VERSION 5.8 ;
BUSBITCHARS "[]" ;
DIVIDERCHAR "/" ;
UNITS
    DATABASE MICRONS 1000 ;
END UNITS

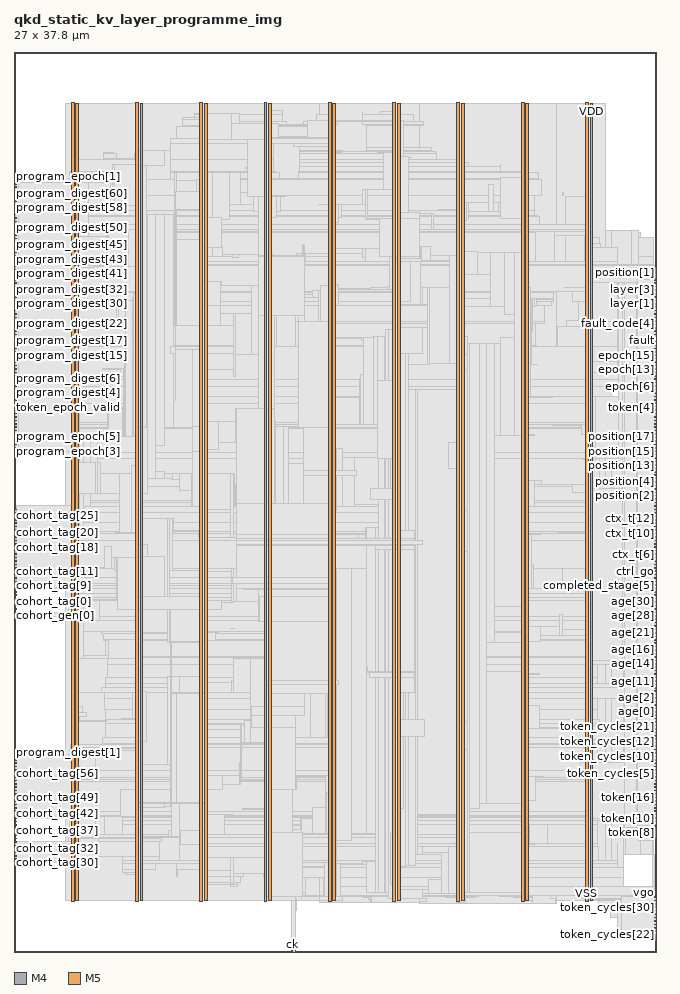
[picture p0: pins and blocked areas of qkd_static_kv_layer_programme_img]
MACRO qkd_static_kv_layer_programme_img
  FOREIGN qkd_static_kv_layer_programme_img 0 0 ;
  CLASS BLOCK ;
  SIZE 27 BY 37.8 ;
  PIN active
    DIRECTION OUTPUT ;
    USE SIGNAL ;
    PORT
      LAYER M4 ;
        RECT  26.916 9.936 27 9.96 ;
    END
  END active
  PIN age[0]
    DIRECTION OUTPUT ;
    USE SIGNAL ;
    PORT
      LAYER M4 ;
        RECT  26.916 10.08 27 10.104 ;
    END
  END age[0]
  PIN age[10]
    DIRECTION OUTPUT ;
    USE SIGNAL ;
    PORT
      LAYER M4 ;
        RECT  26.916 11.52 27 11.544 ;
    END
  END age[10]
  PIN age[11]
    DIRECTION OUTPUT ;
    USE SIGNAL ;
    PORT
      LAYER M4 ;
        RECT  26.916 11.664 27 11.688 ;
    END
  END age[11]
  PIN age[12]
    DIRECTION OUTPUT ;
    USE SIGNAL ;
    PORT
      LAYER M4 ;
        RECT  26.916 11.808 27 11.832 ;
    END
  END age[12]
  PIN age[13]
    DIRECTION OUTPUT ;
    USE SIGNAL ;
    PORT
      LAYER M4 ;
        RECT  26.916 11.952 27 11.976 ;
    END
  END age[13]
  PIN age[14]
    DIRECTION OUTPUT ;
    USE SIGNAL ;
    PORT
      LAYER M4 ;
        RECT  26.916 12.096 27 12.12 ;
    END
  END age[14]
  PIN age[15]
    DIRECTION OUTPUT ;
    USE SIGNAL ;
    PORT
      LAYER M4 ;
        RECT  26.916 12.24 27 12.264 ;
    END
  END age[15]
  PIN age[16]
    DIRECTION OUTPUT ;
    USE SIGNAL ;
    PORT
      LAYER M4 ;
        RECT  26.916 12.384 27 12.408 ;
    END
  END age[16]
  PIN age[17]
    DIRECTION OUTPUT ;
    USE SIGNAL ;
    PORT
      LAYER M4 ;
        RECT  26.916 12.528 27 12.552 ;
    END
  END age[17]
  PIN age[18]
    DIRECTION OUTPUT ;
    USE SIGNAL ;
    PORT
      LAYER M4 ;
        RECT  26.916 12.672 27 12.696 ;
    END
  END age[18]
  PIN age[19]
    DIRECTION OUTPUT ;
    USE SIGNAL ;
    PORT
      LAYER M4 ;
        RECT  26.916 12.816 27 12.84 ;
    END
  END age[19]
  PIN age[1]
    DIRECTION OUTPUT ;
    USE SIGNAL ;
    PORT
      LAYER M4 ;
        RECT  26.916 10.224 27 10.248 ;
    END
  END age[1]
  PIN age[20]
    DIRECTION OUTPUT ;
    USE SIGNAL ;
    PORT
      LAYER M4 ;
        RECT  26.916 12.96 27 12.984 ;
    END
  END age[20]
  PIN age[21]
    DIRECTION OUTPUT ;
    USE SIGNAL ;
    PORT
      LAYER M4 ;
        RECT  26.916 13.104 27 13.128 ;
    END
  END age[21]
  PIN age[22]
    DIRECTION OUTPUT ;
    USE SIGNAL ;
    PORT
      LAYER M4 ;
        RECT  26.916 13.248 27 13.272 ;
    END
  END age[22]
  PIN age[23]
    DIRECTION OUTPUT ;
    USE SIGNAL ;
    PORT
      LAYER M4 ;
        RECT  26.916 13.392 27 13.416 ;
    END
  END age[23]
  PIN age[24]
    DIRECTION OUTPUT ;
    USE SIGNAL ;
    PORT
      LAYER M4 ;
        RECT  26.916 13.536 27 13.56 ;
    END
  END age[24]
  PIN age[25]
    DIRECTION OUTPUT ;
    USE SIGNAL ;
    PORT
      LAYER M4 ;
        RECT  26.916 13.68 27 13.704 ;
    END
  END age[25]
  PIN age[26]
    DIRECTION OUTPUT ;
    USE SIGNAL ;
    PORT
      LAYER M4 ;
        RECT  26.916 13.824 27 13.848 ;
    END
  END age[26]
  PIN age[27]
    DIRECTION OUTPUT ;
    USE SIGNAL ;
    PORT
      LAYER M4 ;
        RECT  26.916 13.968 27 13.992 ;
    END
  END age[27]
  PIN age[28]
    DIRECTION OUTPUT ;
    USE SIGNAL ;
    PORT
      LAYER M4 ;
        RECT  26.916 14.112 27 14.136 ;
    END
  END age[28]
  PIN age[29]
    DIRECTION OUTPUT ;
    USE SIGNAL ;
    PORT
      LAYER M4 ;
        RECT  26.916 14.256 27 14.28 ;
    END
  END age[29]
  PIN age[2]
    DIRECTION OUTPUT ;
    USE SIGNAL ;
    PORT
      LAYER M4 ;
        RECT  26.916 10.368 27 10.392 ;
    END
  END age[2]
  PIN age[30]
    DIRECTION OUTPUT ;
    USE SIGNAL ;
    PORT
      LAYER M4 ;
        RECT  26.916 14.4 27 14.424 ;
    END
  END age[30]
  PIN age[31]
    DIRECTION OUTPUT ;
    USE SIGNAL ;
    PORT
      LAYER M4 ;
        RECT  26.916 14.544 27 14.568 ;
    END
  END age[31]
  PIN age[3]
    DIRECTION OUTPUT ;
    USE SIGNAL ;
    PORT
      LAYER M4 ;
        RECT  26.916 10.512 27 10.536 ;
    END
  END age[3]
  PIN age[4]
    DIRECTION OUTPUT ;
    USE SIGNAL ;
    PORT
      LAYER M4 ;
        RECT  26.916 10.656 27 10.68 ;
    END
  END age[4]
  PIN age[5]
    DIRECTION OUTPUT ;
    USE SIGNAL ;
    PORT
      LAYER M4 ;
        RECT  26.916 10.8 27 10.824 ;
    END
  END age[5]
  PIN age[6]
    DIRECTION OUTPUT ;
    USE SIGNAL ;
    PORT
      LAYER M4 ;
        RECT  26.916 10.944 27 10.968 ;
    END
  END age[6]
  PIN age[7]
    DIRECTION OUTPUT ;
    USE SIGNAL ;
    PORT
      LAYER M4 ;
        RECT  26.916 11.088 27 11.112 ;
    END
  END age[7]
  PIN age[8]
    DIRECTION OUTPUT ;
    USE SIGNAL ;
    PORT
      LAYER M4 ;
        RECT  26.916 11.232 27 11.256 ;
    END
  END age[8]
  PIN age[9]
    DIRECTION OUTPUT ;
    USE SIGNAL ;
    PORT
      LAYER M4 ;
        RECT  26.916 11.376 27 11.4 ;
    END
  END age[9]
  PIN attention_issue
    DIRECTION OUTPUT ;
    USE SIGNAL ;
    PORT
      LAYER M4 ;
        RECT  26.916 14.688 27 14.712 ;
    END
  END attention_issue
  PIN attention_run
    DIRECTION OUTPUT ;
    USE SIGNAL ;
    PORT
      LAYER M4 ;
        RECT  26.916 14.832 27 14.856 ;
    END
  END attention_run
  PIN ck
    DIRECTION INPUT ;
    USE SIGNAL ;
    PORT
      LAYER M5 ;
        RECT  11.664 0 11.688 0.084 ;
    END
  END ck
  PIN cohort_gen[0]
    DIRECTION INPUT ;
    USE SIGNAL ;
    PORT
      LAYER M4 ;
        RECT  0 14.112 0.084 14.136 ;
    END
  END cohort_gen[0]
  PIN cohort_gen[1]
    DIRECTION INPUT ;
    USE SIGNAL ;
    PORT
      LAYER M4 ;
        RECT  0 14.256 0.084 14.28 ;
    END
  END cohort_gen[1]
  PIN cohort_tag[0]
    DIRECTION INPUT ;
    USE SIGNAL ;
    PORT
      LAYER M4 ;
        RECT  0 14.4 0.084 14.424 ;
    END
  END cohort_tag[0]
  PIN cohort_tag[10]
    DIRECTION INPUT ;
    USE SIGNAL ;
    PORT
      LAYER M4 ;
        RECT  0 15.84 0.084 15.864 ;
    END
  END cohort_tag[10]
  PIN cohort_tag[11]
    DIRECTION INPUT ;
    USE SIGNAL ;
    PORT
      LAYER M4 ;
        RECT  0 15.984 0.084 16.008 ;
    END
  END cohort_tag[11]
  PIN cohort_tag[12]
    DIRECTION INPUT ;
    USE SIGNAL ;
    PORT
      LAYER M4 ;
        RECT  0 16.128 0.084 16.152 ;
    END
  END cohort_tag[12]
  PIN cohort_tag[13]
    DIRECTION INPUT ;
    USE SIGNAL ;
    PORT
      LAYER M4 ;
        RECT  0 16.272 0.084 16.296 ;
    END
  END cohort_tag[13]
  PIN cohort_tag[14]
    DIRECTION INPUT ;
    USE SIGNAL ;
    PORT
      LAYER M4 ;
        RECT  0 16.416 0.084 16.44 ;
    END
  END cohort_tag[14]
  PIN cohort_tag[15]
    DIRECTION INPUT ;
    USE SIGNAL ;
    PORT
      LAYER M4 ;
        RECT  0 16.56 0.084 16.584 ;
    END
  END cohort_tag[15]
  PIN cohort_tag[16]
    DIRECTION INPUT ;
    USE SIGNAL ;
    PORT
      LAYER M4 ;
        RECT  0 16.704 0.084 16.728 ;
    END
  END cohort_tag[16]
  PIN cohort_tag[17]
    DIRECTION INPUT ;
    USE SIGNAL ;
    PORT
      LAYER M4 ;
        RECT  0 16.848 0.084 16.872 ;
    END
  END cohort_tag[17]
  PIN cohort_tag[18]
    DIRECTION INPUT ;
    USE SIGNAL ;
    PORT
      LAYER M4 ;
        RECT  0 16.992 0.084 17.016 ;
    END
  END cohort_tag[18]
  PIN cohort_tag[19]
    DIRECTION INPUT ;
    USE SIGNAL ;
    PORT
      LAYER M4 ;
        RECT  0 17.136 0.084 17.16 ;
    END
  END cohort_tag[19]
  PIN cohort_tag[1]
    DIRECTION INPUT ;
    USE SIGNAL ;
    PORT
      LAYER M4 ;
        RECT  0 14.544 0.084 14.568 ;
    END
  END cohort_tag[1]
  PIN cohort_tag[20]
    DIRECTION INPUT ;
    USE SIGNAL ;
    PORT
      LAYER M4 ;
        RECT  0 17.28 0.084 17.304 ;
    END
  END cohort_tag[20]
  PIN cohort_tag[21]
    DIRECTION INPUT ;
    USE SIGNAL ;
    PORT
      LAYER M4 ;
        RECT  0 17.424 0.084 17.448 ;
    END
  END cohort_tag[21]
  PIN cohort_tag[22]
    DIRECTION INPUT ;
    USE SIGNAL ;
    PORT
      LAYER M4 ;
        RECT  0 17.568 0.084 17.592 ;
    END
  END cohort_tag[22]
  PIN cohort_tag[23]
    DIRECTION INPUT ;
    USE SIGNAL ;
    PORT
      LAYER M4 ;
        RECT  0 17.712 0.084 17.736 ;
    END
  END cohort_tag[23]
  PIN cohort_tag[24]
    DIRECTION INPUT ;
    USE SIGNAL ;
    PORT
      LAYER M4 ;
        RECT  0 17.856 0.084 17.88 ;
    END
  END cohort_tag[24]
  PIN cohort_tag[25]
    DIRECTION INPUT ;
    USE SIGNAL ;
    PORT
      LAYER M4 ;
        RECT  0 18 0.084 18.024 ;
    END
  END cohort_tag[25]
  PIN cohort_tag[26]
    DIRECTION INPUT ;
    USE SIGNAL ;
    PORT
      LAYER M4 ;
        RECT  0 18.144 0.084 18.168 ;
    END
  END cohort_tag[26]
  PIN cohort_tag[27]
    DIRECTION INPUT ;
    USE SIGNAL ;
    PORT
      LAYER M4 ;
        RECT  0 18.288 0.084 18.312 ;
    END
  END cohort_tag[27]
  PIN cohort_tag[28]
    DIRECTION INPUT ;
    USE SIGNAL ;
    PORT
      LAYER M4 ;
        RECT  0 18.432 0.084 18.456 ;
    END
  END cohort_tag[28]
  PIN cohort_tag[29]
    DIRECTION INPUT ;
    USE SIGNAL ;
    PORT
      LAYER M4 ;
        RECT  0 18.576 0.084 18.6 ;
    END
  END cohort_tag[29]
  PIN cohort_tag[2]
    DIRECTION INPUT ;
    USE SIGNAL ;
    PORT
      LAYER M4 ;
        RECT  0 14.688 0.084 14.712 ;
    END
  END cohort_tag[2]
  PIN cohort_tag[30]
    DIRECTION INPUT ;
    USE SIGNAL ;
    PORT
      LAYER M4 ;
        RECT  0 3.744 0.084 3.768 ;
    END
  END cohort_tag[30]
  PIN cohort_tag[31]
    DIRECTION INPUT ;
    USE SIGNAL ;
    PORT
      LAYER M4 ;
        RECT  0 3.888 0.084 3.912 ;
    END
  END cohort_tag[31]
  PIN cohort_tag[32]
    DIRECTION INPUT ;
    USE SIGNAL ;
    PORT
      LAYER M4 ;
        RECT  0 4.032 0.084 4.056 ;
    END
  END cohort_tag[32]
  PIN cohort_tag[33]
    DIRECTION INPUT ;
    USE SIGNAL ;
    PORT
      LAYER M4 ;
        RECT  0 4.176 0.084 4.2 ;
    END
  END cohort_tag[33]
  PIN cohort_tag[34]
    DIRECTION INPUT ;
    USE SIGNAL ;
    PORT
      LAYER M4 ;
        RECT  0 4.32 0.084 4.344 ;
    END
  END cohort_tag[34]
  PIN cohort_tag[35]
    DIRECTION INPUT ;
    USE SIGNAL ;
    PORT
      LAYER M4 ;
        RECT  0 4.464 0.084 4.488 ;
    END
  END cohort_tag[35]
  PIN cohort_tag[36]
    DIRECTION INPUT ;
    USE SIGNAL ;
    PORT
      LAYER M4 ;
        RECT  0 4.608 0.084 4.632 ;
    END
  END cohort_tag[36]
  PIN cohort_tag[37]
    DIRECTION INPUT ;
    USE SIGNAL ;
    PORT
      LAYER M4 ;
        RECT  0 4.752 0.084 4.776 ;
    END
  END cohort_tag[37]
  PIN cohort_tag[38]
    DIRECTION INPUT ;
    USE SIGNAL ;
    PORT
      LAYER M4 ;
        RECT  0 4.896 0.084 4.92 ;
    END
  END cohort_tag[38]
  PIN cohort_tag[39]
    DIRECTION INPUT ;
    USE SIGNAL ;
    PORT
      LAYER M4 ;
        RECT  0 5.04 0.084 5.064 ;
    END
  END cohort_tag[39]
  PIN cohort_tag[3]
    DIRECTION INPUT ;
    USE SIGNAL ;
    PORT
      LAYER M4 ;
        RECT  0 14.832 0.084 14.856 ;
    END
  END cohort_tag[3]
  PIN cohort_tag[40]
    DIRECTION INPUT ;
    USE SIGNAL ;
    PORT
      LAYER M4 ;
        RECT  0 5.184 0.084 5.208 ;
    END
  END cohort_tag[40]
  PIN cohort_tag[41]
    DIRECTION INPUT ;
    USE SIGNAL ;
    PORT
      LAYER M4 ;
        RECT  0 5.328 0.084 5.352 ;
    END
  END cohort_tag[41]
  PIN cohort_tag[42]
    DIRECTION INPUT ;
    USE SIGNAL ;
    PORT
      LAYER M4 ;
        RECT  0 5.472 0.084 5.496 ;
    END
  END cohort_tag[42]
  PIN cohort_tag[43]
    DIRECTION INPUT ;
    USE SIGNAL ;
    PORT
      LAYER M4 ;
        RECT  0 5.616 0.084 5.64 ;
    END
  END cohort_tag[43]
  PIN cohort_tag[44]
    DIRECTION INPUT ;
    USE SIGNAL ;
    PORT
      LAYER M4 ;
        RECT  0 5.76 0.084 5.784 ;
    END
  END cohort_tag[44]
  PIN cohort_tag[45]
    DIRECTION INPUT ;
    USE SIGNAL ;
    PORT
      LAYER M4 ;
        RECT  0 5.904 0.084 5.928 ;
    END
  END cohort_tag[45]
  PIN cohort_tag[46]
    DIRECTION INPUT ;
    USE SIGNAL ;
    PORT
      LAYER M4 ;
        RECT  0 6.048 0.084 6.072 ;
    END
  END cohort_tag[46]
  PIN cohort_tag[47]
    DIRECTION INPUT ;
    USE SIGNAL ;
    PORT
      LAYER M4 ;
        RECT  0 6.192 0.084 6.216 ;
    END
  END cohort_tag[47]
  PIN cohort_tag[48]
    DIRECTION INPUT ;
    USE SIGNAL ;
    PORT
      LAYER M4 ;
        RECT  0 6.336 0.084 6.36 ;
    END
  END cohort_tag[48]
  PIN cohort_tag[49]
    DIRECTION INPUT ;
    USE SIGNAL ;
    PORT
      LAYER M4 ;
        RECT  0 6.48 0.084 6.504 ;
    END
  END cohort_tag[49]
  PIN cohort_tag[4]
    DIRECTION INPUT ;
    USE SIGNAL ;
    PORT
      LAYER M4 ;
        RECT  0 14.976 0.084 15 ;
    END
  END cohort_tag[4]
  PIN cohort_tag[50]
    DIRECTION INPUT ;
    USE SIGNAL ;
    PORT
      LAYER M4 ;
        RECT  0 6.624 0.084 6.648 ;
    END
  END cohort_tag[50]
  PIN cohort_tag[51]
    DIRECTION INPUT ;
    USE SIGNAL ;
    PORT
      LAYER M4 ;
        RECT  0 6.768 0.084 6.792 ;
    END
  END cohort_tag[51]
  PIN cohort_tag[52]
    DIRECTION INPUT ;
    USE SIGNAL ;
    PORT
      LAYER M4 ;
        RECT  0 6.912 0.084 6.936 ;
    END
  END cohort_tag[52]
  PIN cohort_tag[53]
    DIRECTION INPUT ;
    USE SIGNAL ;
    PORT
      LAYER M4 ;
        RECT  0 7.056 0.084 7.08 ;
    END
  END cohort_tag[53]
  PIN cohort_tag[54]
    DIRECTION INPUT ;
    USE SIGNAL ;
    PORT
      LAYER M4 ;
        RECT  0 7.2 0.084 7.224 ;
    END
  END cohort_tag[54]
  PIN cohort_tag[55]
    DIRECTION INPUT ;
    USE SIGNAL ;
    PORT
      LAYER M4 ;
        RECT  0 7.344 0.084 7.368 ;
    END
  END cohort_tag[55]
  PIN cohort_tag[56]
    DIRECTION INPUT ;
    USE SIGNAL ;
    PORT
      LAYER M4 ;
        RECT  0 7.488 0.084 7.512 ;
    END
  END cohort_tag[56]
  PIN cohort_tag[57]
    DIRECTION INPUT ;
    USE SIGNAL ;
    PORT
      LAYER M4 ;
        RECT  0 7.632 0.084 7.656 ;
    END
  END cohort_tag[57]
  PIN cohort_tag[58]
    DIRECTION INPUT ;
    USE SIGNAL ;
    PORT
      LAYER M4 ;
        RECT  0 7.776 0.084 7.8 ;
    END
  END cohort_tag[58]
  PIN cohort_tag[5]
    DIRECTION INPUT ;
    USE SIGNAL ;
    PORT
      LAYER M4 ;
        RECT  0 15.12 0.084 15.144 ;
    END
  END cohort_tag[5]
  PIN cohort_tag[6]
    DIRECTION INPUT ;
    USE SIGNAL ;
    PORT
      LAYER M4 ;
        RECT  0 15.264 0.084 15.288 ;
    END
  END cohort_tag[6]
  PIN cohort_tag[7]
    DIRECTION INPUT ;
    USE SIGNAL ;
    PORT
      LAYER M4 ;
        RECT  0 15.408 0.084 15.432 ;
    END
  END cohort_tag[7]
  PIN cohort_tag[8]
    DIRECTION INPUT ;
    USE SIGNAL ;
    PORT
      LAYER M4 ;
        RECT  0 15.552 0.084 15.576 ;
    END
  END cohort_tag[8]
  PIN cohort_tag[9]
    DIRECTION INPUT ;
    USE SIGNAL ;
    PORT
      LAYER M4 ;
        RECT  0 15.696 0.084 15.72 ;
    END
  END cohort_tag[9]
  PIN completed_stage[0]
    DIRECTION OUTPUT ;
    USE SIGNAL ;
    PORT
      LAYER M4 ;
        RECT  26.916 14.976 27 15 ;
    END
  END completed_stage[0]
  PIN completed_stage[1]
    DIRECTION OUTPUT ;
    USE SIGNAL ;
    PORT
      LAYER M4 ;
        RECT  26.916 15.12 27 15.144 ;
    END
  END completed_stage[1]
  PIN completed_stage[2]
    DIRECTION OUTPUT ;
    USE SIGNAL ;
    PORT
      LAYER M4 ;
        RECT  26.916 15.264 27 15.288 ;
    END
  END completed_stage[2]
  PIN completed_stage[3]
    DIRECTION OUTPUT ;
    USE SIGNAL ;
    PORT
      LAYER M4 ;
        RECT  26.916 15.408 27 15.432 ;
    END
  END completed_stage[3]
  PIN completed_stage[4]
    DIRECTION OUTPUT ;
    USE SIGNAL ;
    PORT
      LAYER M4 ;
        RECT  26.916 15.552 27 15.576 ;
    END
  END completed_stage[4]
  PIN completed_stage[5]
    DIRECTION OUTPUT ;
    USE SIGNAL ;
    PORT
      LAYER M4 ;
        RECT  26.916 15.696 27 15.72 ;
    END
  END completed_stage[5]
  PIN configured
    DIRECTION OUTPUT ;
    USE SIGNAL ;
    PORT
      LAYER M4 ;
        RECT  26.916 15.84 27 15.864 ;
    END
  END configured
  PIN ctrl_go
    DIRECTION OUTPUT ;
    USE SIGNAL ;
    PORT
      LAYER M4 ;
        RECT  26.916 15.984 27 16.008 ;
    END
  END ctrl_go
  PIN ctx_t[0]
    DIRECTION OUTPUT ;
    USE SIGNAL ;
    PORT
      LAYER M4 ;
        RECT  26.916 16.128 27 16.152 ;
    END
  END ctx_t[0]
  PIN ctx_t[10]
    DIRECTION OUTPUT ;
    USE SIGNAL ;
    PORT
      LAYER M4 ;
        RECT  26.916 17.568 27 17.592 ;
    END
  END ctx_t[10]
  PIN ctx_t[11]
    DIRECTION OUTPUT ;
    USE SIGNAL ;
    PORT
      LAYER M4 ;
        RECT  26.916 17.712 27 17.736 ;
    END
  END ctx_t[11]
  PIN ctx_t[12]
    DIRECTION OUTPUT ;
    USE SIGNAL ;
    PORT
      LAYER M4 ;
        RECT  26.916 17.856 27 17.88 ;
    END
  END ctx_t[12]
  PIN ctx_t[13]
    DIRECTION OUTPUT ;
    USE SIGNAL ;
    PORT
      LAYER M4 ;
        RECT  26.916 18 27 18.024 ;
    END
  END ctx_t[13]
  PIN ctx_t[1]
    DIRECTION OUTPUT ;
    USE SIGNAL ;
    PORT
      LAYER M4 ;
        RECT  26.916 16.272 27 16.296 ;
    END
  END ctx_t[1]
  PIN ctx_t[2]
    DIRECTION OUTPUT ;
    USE SIGNAL ;
    PORT
      LAYER M4 ;
        RECT  26.916 16.416 27 16.44 ;
    END
  END ctx_t[2]
  PIN ctx_t[3]
    DIRECTION OUTPUT ;
    USE SIGNAL ;
    PORT
      LAYER M4 ;
        RECT  26.916 16.56 27 16.584 ;
    END
  END ctx_t[3]
  PIN ctx_t[4]
    DIRECTION OUTPUT ;
    USE SIGNAL ;
    PORT
      LAYER M4 ;
        RECT  26.916 16.704 27 16.728 ;
    END
  END ctx_t[4]
  PIN ctx_t[5]
    DIRECTION OUTPUT ;
    USE SIGNAL ;
    PORT
      LAYER M4 ;
        RECT  26.916 16.848 27 16.872 ;
    END
  END ctx_t[5]
  PIN ctx_t[6]
    DIRECTION OUTPUT ;
    USE SIGNAL ;
    PORT
      LAYER M4 ;
        RECT  26.916 16.992 27 17.016 ;
    END
  END ctx_t[6]
  PIN ctx_t[7]
    DIRECTION OUTPUT ;
    USE SIGNAL ;
    PORT
      LAYER M4 ;
        RECT  26.916 17.136 27 17.16 ;
    END
  END ctx_t[7]
  PIN ctx_t[8]
    DIRECTION OUTPUT ;
    USE SIGNAL ;
    PORT
      LAYER M4 ;
        RECT  26.916 17.28 27 17.304 ;
    END
  END ctx_t[8]
  PIN ctx_t[9]
    DIRECTION OUTPUT ;
    USE SIGNAL ;
    PORT
      LAYER M4 ;
        RECT  26.916 17.424 27 17.448 ;
    END
  END ctx_t[9]
  PIN done
    DIRECTION OUTPUT ;
    USE SIGNAL ;
    PORT
      LAYER M4 ;
        RECT  26.916 18.144 27 18.168 ;
    END
  END done
  PIN epoch[0]
    DIRECTION OUTPUT ;
    USE SIGNAL ;
    PORT
      LAYER M4 ;
        RECT  26.916 18.288 27 18.312 ;
    END
  END epoch[0]
  PIN epoch[10]
    DIRECTION OUTPUT ;
    USE SIGNAL ;
    PORT
      LAYER M4 ;
        RECT  26.916 24.336 27 24.36 ;
    END
  END epoch[10]
  PIN epoch[11]
    DIRECTION OUTPUT ;
    USE SIGNAL ;
    PORT
      LAYER M4 ;
        RECT  26.916 24.48 27 24.504 ;
    END
  END epoch[11]
  PIN epoch[12]
    DIRECTION OUTPUT ;
    USE SIGNAL ;
    PORT
      LAYER M4 ;
        RECT  26.916 24.624 27 24.648 ;
    END
  END epoch[12]
  PIN epoch[13]
    DIRECTION OUTPUT ;
    USE SIGNAL ;
    PORT
      LAYER M4 ;
        RECT  26.916 24.768 27 24.792 ;
    END
  END epoch[13]
  PIN epoch[14]
    DIRECTION OUTPUT ;
    USE SIGNAL ;
    PORT
      LAYER M4 ;
        RECT  26.916 24.912 27 24.936 ;
    END
  END epoch[14]
  PIN epoch[15]
    DIRECTION OUTPUT ;
    USE SIGNAL ;
    PORT
      LAYER M4 ;
        RECT  26.916 25.056 27 25.08 ;
    END
  END epoch[15]
  PIN epoch[1]
    DIRECTION OUTPUT ;
    USE SIGNAL ;
    PORT
      LAYER M4 ;
        RECT  26.916 18.432 27 18.456 ;
    END
  END epoch[1]
  PIN epoch[2]
    DIRECTION OUTPUT ;
    USE SIGNAL ;
    PORT
      LAYER M4 ;
        RECT  26.916 18.576 27 18.6 ;
    END
  END epoch[2]
  PIN epoch[3]
    DIRECTION OUTPUT ;
    USE SIGNAL ;
    PORT
      LAYER M4 ;
        RECT  26.916 18.72 27 18.744 ;
    END
  END epoch[3]
  PIN epoch[4]
    DIRECTION OUTPUT ;
    USE SIGNAL ;
    PORT
      LAYER M4 ;
        RECT  26.916 18.864 27 18.888 ;
    END
  END epoch[4]
  PIN epoch[5]
    DIRECTION OUTPUT ;
    USE SIGNAL ;
    PORT
      LAYER M4 ;
        RECT  26.916 19.008 27 19.032 ;
    END
  END epoch[5]
  PIN epoch[6]
    DIRECTION OUTPUT ;
    USE SIGNAL ;
    PORT
      LAYER M4 ;
        RECT  26.916 23.76 27 23.784 ;
    END
  END epoch[6]
  PIN epoch[7]
    DIRECTION OUTPUT ;
    USE SIGNAL ;
    PORT
      LAYER M4 ;
        RECT  26.916 23.904 27 23.928 ;
    END
  END epoch[7]
  PIN epoch[8]
    DIRECTION OUTPUT ;
    USE SIGNAL ;
    PORT
      LAYER M4 ;
        RECT  26.916 24.048 27 24.072 ;
    END
  END epoch[8]
  PIN epoch[9]
    DIRECTION OUTPUT ;
    USE SIGNAL ;
    PORT
      LAYER M4 ;
        RECT  26.916 24.192 27 24.216 ;
    END
  END epoch[9]
  PIN expected_upstream_quiet
    DIRECTION OUTPUT ;
    USE SIGNAL ;
    PORT
      LAYER M4 ;
        RECT  26.916 25.2 27 25.224 ;
    END
  END expected_upstream_quiet
  PIN fault
    DIRECTION OUTPUT ;
    USE SIGNAL ;
    PORT
      LAYER M4 ;
        RECT  26.916 25.344 27 25.368 ;
    END
  END fault
  PIN fault_code[0]
    DIRECTION OUTPUT ;
    USE SIGNAL ;
    PORT
      LAYER M4 ;
        RECT  26.916 25.488 27 25.512 ;
    END
  END fault_code[0]
  PIN fault_code[1]
    DIRECTION OUTPUT ;
    USE SIGNAL ;
    PORT
      LAYER M4 ;
        RECT  26.916 25.632 27 25.656 ;
    END
  END fault_code[1]
  PIN fault_code[2]
    DIRECTION OUTPUT ;
    USE SIGNAL ;
    PORT
      LAYER M4 ;
        RECT  26.916 25.776 27 25.8 ;
    END
  END fault_code[2]
  PIN fault_code[3]
    DIRECTION OUTPUT ;
    USE SIGNAL ;
    PORT
      LAYER M4 ;
        RECT  26.916 25.92 27 25.944 ;
    END
  END fault_code[3]
  PIN fault_code[4]
    DIRECTION OUTPUT ;
    USE SIGNAL ;
    PORT
      LAYER M4 ;
        RECT  26.916 26.064 27 26.088 ;
    END
  END fault_code[4]
  PIN fault_code[5]
    DIRECTION OUTPUT ;
    USE SIGNAL ;
    PORT
      LAYER M4 ;
        RECT  26.916 26.208 27 26.232 ;
    END
  END fault_code[5]
  PIN fault_code[6]
    DIRECTION OUTPUT ;
    USE SIGNAL ;
    PORT
      LAYER M4 ;
        RECT  26.916 26.352 27 26.376 ;
    END
  END fault_code[6]
  PIN fault_code[7]
    DIRECTION OUTPUT ;
    USE SIGNAL ;
    PORT
      LAYER M4 ;
        RECT  26.916 26.496 27 26.52 ;
    END
  END fault_code[7]
  PIN generation[0]
    DIRECTION OUTPUT ;
    USE SIGNAL ;
    PORT
      LAYER M4 ;
        RECT  26.916 26.64 27 26.664 ;
    END
  END generation[0]
  PIN generation[1]
    DIRECTION OUTPUT ;
    USE SIGNAL ;
    PORT
      LAYER M4 ;
        RECT  26.916 26.784 27 26.808 ;
    END
  END generation[1]
  PIN kgo
    DIRECTION OUTPUT ;
    USE SIGNAL ;
    PORT
      LAYER M4 ;
        RECT  26.916 26.928 27 26.952 ;
    END
  END kgo
  PIN layer[0]
    DIRECTION OUTPUT ;
    USE SIGNAL ;
    PORT
      LAYER M4 ;
        RECT  26.916 27.072 27 27.096 ;
    END
  END layer[0]
  PIN layer[1]
    DIRECTION OUTPUT ;
    USE SIGNAL ;
    PORT
      LAYER M4 ;
        RECT  26.916 27.216 27 27.24 ;
    END
  END layer[1]
  PIN layer[2]
    DIRECTION OUTPUT ;
    USE SIGNAL ;
    PORT
      LAYER M4 ;
        RECT  26.916 27.36 27 27.384 ;
    END
  END layer[2]
  PIN layer[3]
    DIRECTION OUTPUT ;
    USE SIGNAL ;
    PORT
      LAYER M4 ;
        RECT  26.916 27.504 27 27.528 ;
    END
  END layer[3]
  PIN layer[4]
    DIRECTION OUTPUT ;
    USE SIGNAL ;
    PORT
      LAYER M4 ;
        RECT  26.916 27.648 27 27.672 ;
    END
  END layer[4]
  PIN layer[5]
    DIRECTION OUTPUT ;
    USE SIGNAL ;
    PORT
      LAYER M4 ;
        RECT  26.916 27.792 27 27.816 ;
    END
  END layer[5]
  PIN link_start
    DIRECTION OUTPUT ;
    USE SIGNAL ;
    PORT
      LAYER M4 ;
        RECT  26.916 27.936 27 27.96 ;
    END
  END link_start
  PIN position[0]
    DIRECTION OUTPUT ;
    USE SIGNAL ;
    PORT
      LAYER M4 ;
        RECT  26.916 28.08 27 28.104 ;
    END
  END position[0]
  PIN position[10]
    DIRECTION OUTPUT ;
    USE SIGNAL ;
    PORT
      LAYER M4 ;
        RECT  26.916 20.304 27 20.328 ;
    END
  END position[10]
  PIN position[11]
    DIRECTION OUTPUT ;
    USE SIGNAL ;
    PORT
      LAYER M4 ;
        RECT  26.916 20.448 27 20.472 ;
    END
  END position[11]
  PIN position[12]
    DIRECTION OUTPUT ;
    USE SIGNAL ;
    PORT
      LAYER M4 ;
        RECT  26.916 20.592 27 20.616 ;
    END
  END position[12]
  PIN position[13]
    DIRECTION OUTPUT ;
    USE SIGNAL ;
    PORT
      LAYER M4 ;
        RECT  26.916 20.736 27 20.76 ;
    END
  END position[13]
  PIN position[14]
    DIRECTION OUTPUT ;
    USE SIGNAL ;
    PORT
      LAYER M4 ;
        RECT  26.916 20.88 27 20.904 ;
    END
  END position[14]
  PIN position[15]
    DIRECTION OUTPUT ;
    USE SIGNAL ;
    PORT
      LAYER M4 ;
        RECT  26.916 21.024 27 21.048 ;
    END
  END position[15]
  PIN position[16]
    DIRECTION OUTPUT ;
    USE SIGNAL ;
    PORT
      LAYER M4 ;
        RECT  26.916 21.168 27 21.192 ;
    END
  END position[16]
  PIN position[17]
    DIRECTION OUTPUT ;
    USE SIGNAL ;
    PORT
      LAYER M4 ;
        RECT  26.916 21.312 27 21.336 ;
    END
  END position[17]
  PIN position[1]
    DIRECTION OUTPUT ;
    USE SIGNAL ;
    PORT
      LAYER M4 ;
        RECT  26.916 28.224 27 28.248 ;
    END
  END position[1]
  PIN position[2]
    DIRECTION OUTPUT ;
    USE SIGNAL ;
    PORT
      LAYER M4 ;
        RECT  26.916 19.152 27 19.176 ;
    END
  END position[2]
  PIN position[3]
    DIRECTION OUTPUT ;
    USE SIGNAL ;
    PORT
      LAYER M4 ;
        RECT  26.916 19.296 27 19.32 ;
    END
  END position[3]
  PIN position[4]
    DIRECTION OUTPUT ;
    USE SIGNAL ;
    PORT
      LAYER M4 ;
        RECT  26.916 19.44 27 19.464 ;
    END
  END position[4]
  PIN position[5]
    DIRECTION OUTPUT ;
    USE SIGNAL ;
    PORT
      LAYER M4 ;
        RECT  26.916 19.584 27 19.608 ;
    END
  END position[5]
  PIN position[6]
    DIRECTION OUTPUT ;
    USE SIGNAL ;
    PORT
      LAYER M4 ;
        RECT  26.916 19.728 27 19.752 ;
    END
  END position[6]
  PIN position[7]
    DIRECTION OUTPUT ;
    USE SIGNAL ;
    PORT
      LAYER M4 ;
        RECT  26.916 19.872 27 19.896 ;
    END
  END position[7]
  PIN position[8]
    DIRECTION OUTPUT ;
    USE SIGNAL ;
    PORT
      LAYER M4 ;
        RECT  26.916 20.016 27 20.04 ;
    END
  END position[8]
  PIN position[9]
    DIRECTION OUTPUT ;
    USE SIGNAL ;
    PORT
      LAYER M4 ;
        RECT  26.916 20.16 27 20.184 ;
    END
  END position[9]
  PIN program_digest[0]
    DIRECTION INPUT ;
    USE SIGNAL ;
    PORT
      LAYER M4 ;
        RECT  0 7.92 0.084 7.944 ;
    END
  END program_digest[0]
  PIN program_digest[10]
    DIRECTION INPUT ;
    USE SIGNAL ;
    PORT
      LAYER M4 ;
        RECT  0 24.336 0.084 24.36 ;
    END
  END program_digest[10]
  PIN program_digest[11]
    DIRECTION INPUT ;
    USE SIGNAL ;
    PORT
      LAYER M4 ;
        RECT  0 24.48 0.084 24.504 ;
    END
  END program_digest[11]
  PIN program_digest[12]
    DIRECTION INPUT ;
    USE SIGNAL ;
    PORT
      LAYER M4 ;
        RECT  0 24.624 0.084 24.648 ;
    END
  END program_digest[12]
  PIN program_digest[13]
    DIRECTION INPUT ;
    USE SIGNAL ;
    PORT
      LAYER M4 ;
        RECT  0 24.768 0.084 24.792 ;
    END
  END program_digest[13]
  PIN program_digest[14]
    DIRECTION INPUT ;
    USE SIGNAL ;
    PORT
      LAYER M4 ;
        RECT  0 24.912 0.084 24.936 ;
    END
  END program_digest[14]
  PIN program_digest[15]
    DIRECTION INPUT ;
    USE SIGNAL ;
    PORT
      LAYER M4 ;
        RECT  0 25.056 0.084 25.08 ;
    END
  END program_digest[15]
  PIN program_digest[16]
    DIRECTION INPUT ;
    USE SIGNAL ;
    PORT
      LAYER M4 ;
        RECT  0 25.2 0.084 25.224 ;
    END
  END program_digest[16]
  PIN program_digest[17]
    DIRECTION INPUT ;
    USE SIGNAL ;
    PORT
      LAYER M4 ;
        RECT  0 25.344 0.084 25.368 ;
    END
  END program_digest[17]
  PIN program_digest[18]
    DIRECTION INPUT ;
    USE SIGNAL ;
    PORT
      LAYER M4 ;
        RECT  0 25.488 0.084 25.512 ;
    END
  END program_digest[18]
  PIN program_digest[19]
    DIRECTION INPUT ;
    USE SIGNAL ;
    PORT
      LAYER M4 ;
        RECT  0 25.632 0.084 25.656 ;
    END
  END program_digest[19]
  PIN program_digest[1]
    DIRECTION INPUT ;
    USE SIGNAL ;
    PORT
      LAYER M4 ;
        RECT  0 8.064 0.084 8.088 ;
    END
  END program_digest[1]
  PIN program_digest[20]
    DIRECTION INPUT ;
    USE SIGNAL ;
    PORT
      LAYER M4 ;
        RECT  0 25.776 0.084 25.8 ;
    END
  END program_digest[20]
  PIN program_digest[21]
    DIRECTION INPUT ;
    USE SIGNAL ;
    PORT
      LAYER M4 ;
        RECT  0 25.92 0.084 25.944 ;
    END
  END program_digest[21]
  PIN program_digest[22]
    DIRECTION INPUT ;
    USE SIGNAL ;
    PORT
      LAYER M4 ;
        RECT  0 26.064 0.084 26.088 ;
    END
  END program_digest[22]
  PIN program_digest[23]
    DIRECTION INPUT ;
    USE SIGNAL ;
    PORT
      LAYER M4 ;
        RECT  0 26.208 0.084 26.232 ;
    END
  END program_digest[23]
  PIN program_digest[24]
    DIRECTION INPUT ;
    USE SIGNAL ;
    PORT
      LAYER M4 ;
        RECT  0 26.352 0.084 26.376 ;
    END
  END program_digest[24]
  PIN program_digest[25]
    DIRECTION INPUT ;
    USE SIGNAL ;
    PORT
      LAYER M4 ;
        RECT  0 26.496 0.084 26.52 ;
    END
  END program_digest[25]
  PIN program_digest[26]
    DIRECTION INPUT ;
    USE SIGNAL ;
    PORT
      LAYER M4 ;
        RECT  0 26.64 0.084 26.664 ;
    END
  END program_digest[26]
  PIN program_digest[27]
    DIRECTION INPUT ;
    USE SIGNAL ;
    PORT
      LAYER M4 ;
        RECT  0 26.784 0.084 26.808 ;
    END
  END program_digest[27]
  PIN program_digest[28]
    DIRECTION INPUT ;
    USE SIGNAL ;
    PORT
      LAYER M4 ;
        RECT  0 26.928 0.084 26.952 ;
    END
  END program_digest[28]
  PIN program_digest[29]
    DIRECTION INPUT ;
    USE SIGNAL ;
    PORT
      LAYER M4 ;
        RECT  0 27.072 0.084 27.096 ;
    END
  END program_digest[29]
  PIN program_digest[2]
    DIRECTION INPUT ;
    USE SIGNAL ;
    PORT
      LAYER M4 ;
        RECT  0 8.208 0.084 8.232 ;
    END
  END program_digest[2]
  PIN program_digest[30]
    DIRECTION INPUT ;
    USE SIGNAL ;
    PORT
      LAYER M4 ;
        RECT  0 27.216 0.084 27.24 ;
    END
  END program_digest[30]
  PIN program_digest[31]
    DIRECTION INPUT ;
    USE SIGNAL ;
    PORT
      LAYER M4 ;
        RECT  0 27.36 0.084 27.384 ;
    END
  END program_digest[31]
  PIN program_digest[32]
    DIRECTION INPUT ;
    USE SIGNAL ;
    PORT
      LAYER M4 ;
        RECT  0 27.504 0.084 27.528 ;
    END
  END program_digest[32]
  PIN program_digest[33]
    DIRECTION INPUT ;
    USE SIGNAL ;
    PORT
      LAYER M4 ;
        RECT  0 27.648 0.084 27.672 ;
    END
  END program_digest[33]
  PIN program_digest[34]
    DIRECTION INPUT ;
    USE SIGNAL ;
    PORT
      LAYER M4 ;
        RECT  0 27.792 0.084 27.816 ;
    END
  END program_digest[34]
  PIN program_digest[35]
    DIRECTION INPUT ;
    USE SIGNAL ;
    PORT
      LAYER M4 ;
        RECT  0 27.936 0.084 27.96 ;
    END
  END program_digest[35]
  PIN program_digest[36]
    DIRECTION INPUT ;
    USE SIGNAL ;
    PORT
      LAYER M4 ;
        RECT  0 28.08 0.084 28.104 ;
    END
  END program_digest[36]
  PIN program_digest[37]
    DIRECTION INPUT ;
    USE SIGNAL ;
    PORT
      LAYER M4 ;
        RECT  0 28.224 0.084 28.248 ;
    END
  END program_digest[37]
  PIN program_digest[38]
    DIRECTION INPUT ;
    USE SIGNAL ;
    PORT
      LAYER M4 ;
        RECT  0 28.368 0.084 28.392 ;
    END
  END program_digest[38]
  PIN program_digest[39]
    DIRECTION INPUT ;
    USE SIGNAL ;
    PORT
      LAYER M4 ;
        RECT  0 28.512 0.084 28.536 ;
    END
  END program_digest[39]
  PIN program_digest[3]
    DIRECTION INPUT ;
    USE SIGNAL ;
    PORT
      LAYER M4 ;
        RECT  0 23.328 0.084 23.352 ;
    END
  END program_digest[3]
  PIN program_digest[40]
    DIRECTION INPUT ;
    USE SIGNAL ;
    PORT
      LAYER M4 ;
        RECT  0 28.656 0.084 28.68 ;
    END
  END program_digest[40]
  PIN program_digest[41]
    DIRECTION INPUT ;
    USE SIGNAL ;
    PORT
      LAYER M4 ;
        RECT  0 28.8 0.084 28.824 ;
    END
  END program_digest[41]
  PIN program_digest[42]
    DIRECTION INPUT ;
    USE SIGNAL ;
    PORT
      LAYER M4 ;
        RECT  0 28.944 0.084 28.968 ;
    END
  END program_digest[42]
  PIN program_digest[43]
    DIRECTION INPUT ;
    USE SIGNAL ;
    PORT
      LAYER M4 ;
        RECT  0 29.088 0.084 29.112 ;
    END
  END program_digest[43]
  PIN program_digest[44]
    DIRECTION INPUT ;
    USE SIGNAL ;
    PORT
      LAYER M4 ;
        RECT  0 29.232 0.084 29.256 ;
    END
  END program_digest[44]
  PIN program_digest[45]
    DIRECTION INPUT ;
    USE SIGNAL ;
    PORT
      LAYER M4 ;
        RECT  0 29.376 0.084 29.4 ;
    END
  END program_digest[45]
  PIN program_digest[46]
    DIRECTION INPUT ;
    USE SIGNAL ;
    PORT
      LAYER M4 ;
        RECT  0 29.52 0.084 29.544 ;
    END
  END program_digest[46]
  PIN program_digest[47]
    DIRECTION INPUT ;
    USE SIGNAL ;
    PORT
      LAYER M4 ;
        RECT  0 29.664 0.084 29.688 ;
    END
  END program_digest[47]
  PIN program_digest[48]
    DIRECTION INPUT ;
    USE SIGNAL ;
    PORT
      LAYER M4 ;
        RECT  0 29.808 0.084 29.832 ;
    END
  END program_digest[48]
  PIN program_digest[49]
    DIRECTION INPUT ;
    USE SIGNAL ;
    PORT
      LAYER M4 ;
        RECT  0 29.952 0.084 29.976 ;
    END
  END program_digest[49]
  PIN program_digest[4]
    DIRECTION INPUT ;
    USE SIGNAL ;
    PORT
      LAYER M4 ;
        RECT  0 23.472 0.084 23.496 ;
    END
  END program_digest[4]
  PIN program_digest[50]
    DIRECTION INPUT ;
    USE SIGNAL ;
    PORT
      LAYER M4 ;
        RECT  0 30.096 0.084 30.12 ;
    END
  END program_digest[50]
  PIN program_digest[51]
    DIRECTION INPUT ;
    USE SIGNAL ;
    PORT
      LAYER M4 ;
        RECT  0 30.24 0.084 30.264 ;
    END
  END program_digest[51]
  PIN program_digest[52]
    DIRECTION INPUT ;
    USE SIGNAL ;
    PORT
      LAYER M4 ;
        RECT  0 30.384 0.084 30.408 ;
    END
  END program_digest[52]
  PIN program_digest[53]
    DIRECTION INPUT ;
    USE SIGNAL ;
    PORT
      LAYER M4 ;
        RECT  0 30.528 0.084 30.552 ;
    END
  END program_digest[53]
  PIN program_digest[54]
    DIRECTION INPUT ;
    USE SIGNAL ;
    PORT
      LAYER M4 ;
        RECT  0 30.672 0.084 30.696 ;
    END
  END program_digest[54]
  PIN program_digest[55]
    DIRECTION INPUT ;
    USE SIGNAL ;
    PORT
      LAYER M4 ;
        RECT  0 30.816 0.084 30.84 ;
    END
  END program_digest[55]
  PIN program_digest[56]
    DIRECTION INPUT ;
    USE SIGNAL ;
    PORT
      LAYER M4 ;
        RECT  0 30.96 0.084 30.984 ;
    END
  END program_digest[56]
  PIN program_digest[57]
    DIRECTION INPUT ;
    USE SIGNAL ;
    PORT
      LAYER M4 ;
        RECT  0 31.104 0.084 31.128 ;
    END
  END program_digest[57]
  PIN program_digest[58]
    DIRECTION INPUT ;
    USE SIGNAL ;
    PORT
      LAYER M4 ;
        RECT  0 31.248 0.084 31.272 ;
    END
  END program_digest[58]
  PIN program_digest[59]
    DIRECTION INPUT ;
    USE SIGNAL ;
    PORT
      LAYER M4 ;
        RECT  0 31.392 0.084 31.416 ;
    END
  END program_digest[59]
  PIN program_digest[5]
    DIRECTION INPUT ;
    USE SIGNAL ;
    PORT
      LAYER M4 ;
        RECT  0 23.616 0.084 23.64 ;
    END
  END program_digest[5]
  PIN program_digest[60]
    DIRECTION INPUT ;
    USE SIGNAL ;
    PORT
      LAYER M4 ;
        RECT  0 31.536 0.084 31.56 ;
    END
  END program_digest[60]
  PIN program_digest[61]
    DIRECTION INPUT ;
    USE SIGNAL ;
    PORT
      LAYER M4 ;
        RECT  0 31.68 0.084 31.704 ;
    END
  END program_digest[61]
  PIN program_digest[62]
    DIRECTION INPUT ;
    USE SIGNAL ;
    PORT
      LAYER M4 ;
        RECT  0 31.824 0.084 31.848 ;
    END
  END program_digest[62]
  PIN program_digest[63]
    DIRECTION INPUT ;
    USE SIGNAL ;
    PORT
      LAYER M4 ;
        RECT  0 31.968 0.084 31.992 ;
    END
  END program_digest[63]
  PIN program_digest[6]
    DIRECTION INPUT ;
    USE SIGNAL ;
    PORT
      LAYER M4 ;
        RECT  0 23.76 0.084 23.784 ;
    END
  END program_digest[6]
  PIN program_digest[7]
    DIRECTION INPUT ;
    USE SIGNAL ;
    PORT
      LAYER M4 ;
        RECT  0 23.904 0.084 23.928 ;
    END
  END program_digest[7]
  PIN program_digest[8]
    DIRECTION INPUT ;
    USE SIGNAL ;
    PORT
      LAYER M4 ;
        RECT  0 24.048 0.084 24.072 ;
    END
  END program_digest[8]
  PIN program_digest[9]
    DIRECTION INPUT ;
    USE SIGNAL ;
    PORT
      LAYER M4 ;
        RECT  0 24.192 0.084 24.216 ;
    END
  END program_digest[9]
  PIN program_epoch[0]
    DIRECTION INPUT ;
    USE SIGNAL ;
    PORT
      LAYER M4 ;
        RECT  0 32.112 0.084 32.136 ;
    END
  END program_epoch[0]
  PIN program_epoch[10]
    DIRECTION INPUT ;
    USE SIGNAL ;
    PORT
      LAYER M4 ;
        RECT  0 22.032 0.084 22.056 ;
    END
  END program_epoch[10]
  PIN program_epoch[11]
    DIRECTION INPUT ;
    USE SIGNAL ;
    PORT
      LAYER M4 ;
        RECT  0 22.176 0.084 22.2 ;
    END
  END program_epoch[11]
  PIN program_epoch[12]
    DIRECTION INPUT ;
    USE SIGNAL ;
    PORT
      LAYER M4 ;
        RECT  0 22.32 0.084 22.344 ;
    END
  END program_epoch[12]
  PIN program_epoch[13]
    DIRECTION INPUT ;
    USE SIGNAL ;
    PORT
      LAYER M4 ;
        RECT  0 22.464 0.084 22.488 ;
    END
  END program_epoch[13]
  PIN program_epoch[14]
    DIRECTION INPUT ;
    USE SIGNAL ;
    PORT
      LAYER M4 ;
        RECT  0 22.608 0.084 22.632 ;
    END
  END program_epoch[14]
  PIN program_epoch[15]
    DIRECTION INPUT ;
    USE SIGNAL ;
    PORT
      LAYER M4 ;
        RECT  0 22.752 0.084 22.776 ;
    END
  END program_epoch[15]
  PIN program_epoch[1]
    DIRECTION INPUT ;
    USE SIGNAL ;
    PORT
      LAYER M4 ;
        RECT  0 32.256 0.084 32.28 ;
    END
  END program_epoch[1]
  PIN program_epoch[2]
    DIRECTION INPUT ;
    USE SIGNAL ;
    PORT
      LAYER M4 ;
        RECT  0 32.4 0.084 32.424 ;
    END
  END program_epoch[2]
  PIN program_epoch[3]
    DIRECTION INPUT ;
    USE SIGNAL ;
    PORT
      LAYER M4 ;
        RECT  0 21.024 0.084 21.048 ;
    END
  END program_epoch[3]
  PIN program_epoch[4]
    DIRECTION INPUT ;
    USE SIGNAL ;
    PORT
      LAYER M4 ;
        RECT  0 21.168 0.084 21.192 ;
    END
  END program_epoch[4]
  PIN program_epoch[5]
    DIRECTION INPUT ;
    USE SIGNAL ;
    PORT
      LAYER M4 ;
        RECT  0 21.312 0.084 21.336 ;
    END
  END program_epoch[5]
  PIN program_epoch[6]
    DIRECTION INPUT ;
    USE SIGNAL ;
    PORT
      LAYER M4 ;
        RECT  0 21.456 0.084 21.48 ;
    END
  END program_epoch[6]
  PIN program_epoch[7]
    DIRECTION INPUT ;
    USE SIGNAL ;
    PORT
      LAYER M4 ;
        RECT  0 21.6 0.084 21.624 ;
    END
  END program_epoch[7]
  PIN program_epoch[8]
    DIRECTION INPUT ;
    USE SIGNAL ;
    PORT
      LAYER M4 ;
        RECT  0 21.744 0.084 21.768 ;
    END
  END program_epoch[8]
  PIN program_epoch[9]
    DIRECTION INPUT ;
    USE SIGNAL ;
    PORT
      LAYER M4 ;
        RECT  0 21.888 0.084 21.912 ;
    END
  END program_epoch[9]
  PIN program_ready
    DIRECTION INPUT ;
    USE SIGNAL ;
    PORT
      LAYER M4 ;
        RECT  0 22.896 0.084 22.92 ;
    END
  END program_ready
  PIN rst_n
    DIRECTION INPUT ;
    USE SIGNAL ;
    PORT
      LAYER M5 ;
        RECT  11.808 0 11.832 0.084 ;
    END
  END rst_n
  PIN stage[0]
    DIRECTION OUTPUT ;
    USE SIGNAL ;
    PORT
      LAYER M4 ;
        RECT  26.916 21.456 27 21.48 ;
    END
  END stage[0]
  PIN stage[1]
    DIRECTION OUTPUT ;
    USE SIGNAL ;
    PORT
      LAYER M4 ;
        RECT  26.916 21.6 27 21.624 ;
    END
  END stage[1]
  PIN stage[2]
    DIRECTION OUTPUT ;
    USE SIGNAL ;
    PORT
      LAYER M4 ;
        RECT  26.916 21.744 27 21.768 ;
    END
  END stage[2]
  PIN stage[3]
    DIRECTION OUTPUT ;
    USE SIGNAL ;
    PORT
      LAYER M4 ;
        RECT  26.916 21.888 27 21.912 ;
    END
  END stage[3]
  PIN stage[4]
    DIRECTION OUTPUT ;
    USE SIGNAL ;
    PORT
      LAYER M4 ;
        RECT  26.916 22.032 27 22.056 ;
    END
  END stage[4]
  PIN stage[5]
    DIRECTION OUTPUT ;
    USE SIGNAL ;
    PORT
      LAYER M4 ;
        RECT  26.916 22.176 27 22.2 ;
    END
  END stage[5]
  PIN stage_done
    DIRECTION OUTPUT ;
    USE SIGNAL ;
    PORT
      LAYER M4 ;
        RECT  26.916 22.32 27 22.344 ;
    END
  END stage_done
  PIN stage_start
    DIRECTION OUTPUT ;
    USE SIGNAL ;
    PORT
      LAYER M4 ;
        RECT  26.916 22.464 27 22.488 ;
    END
  END stage_start
  PIN start
    DIRECTION INPUT ;
    USE SIGNAL ;
    PORT
      LAYER M4 ;
        RECT  0 23.04 0.084 23.064 ;
    END
  END start
  PIN token[0]
    DIRECTION OUTPUT ;
    USE SIGNAL ;
    PORT
      LAYER M4 ;
        RECT  26.916 22.608 27 22.632 ;
    END
  END token[0]
  PIN token[10]
    DIRECTION OUTPUT ;
    USE SIGNAL ;
    PORT
      LAYER M4 ;
        RECT  26.916 5.616 27 5.64 ;
    END
  END token[10]
  PIN token[11]
    DIRECTION OUTPUT ;
    USE SIGNAL ;
    PORT
      LAYER M4 ;
        RECT  26.916 5.76 27 5.784 ;
    END
  END token[11]
  PIN token[12]
    DIRECTION OUTPUT ;
    USE SIGNAL ;
    PORT
      LAYER M4 ;
        RECT  26.916 5.904 27 5.928 ;
    END
  END token[12]
  PIN token[13]
    DIRECTION OUTPUT ;
    USE SIGNAL ;
    PORT
      LAYER M4 ;
        RECT  26.916 6.048 27 6.072 ;
    END
  END token[13]
  PIN token[14]
    DIRECTION OUTPUT ;
    USE SIGNAL ;
    PORT
      LAYER M4 ;
        RECT  26.916 6.192 27 6.216 ;
    END
  END token[14]
  PIN token[15]
    DIRECTION OUTPUT ;
    USE SIGNAL ;
    PORT
      LAYER M4 ;
        RECT  26.916 6.336 27 6.36 ;
    END
  END token[15]
  PIN token[16]
    DIRECTION OUTPUT ;
    USE SIGNAL ;
    PORT
      LAYER M4 ;
        RECT  26.916 6.48 27 6.504 ;
    END
  END token[16]
  PIN token[17]
    DIRECTION OUTPUT ;
    USE SIGNAL ;
    PORT
      LAYER M4 ;
        RECT  26.916 6.624 27 6.648 ;
    END
  END token[17]
  PIN token[1]
    DIRECTION OUTPUT ;
    USE SIGNAL ;
    PORT
      LAYER M4 ;
        RECT  26.916 22.752 27 22.776 ;
    END
  END token[1]
  PIN token[2]
    DIRECTION OUTPUT ;
    USE SIGNAL ;
    PORT
      LAYER M4 ;
        RECT  26.916 22.896 27 22.92 ;
    END
  END token[2]
  PIN token[3]
    DIRECTION OUTPUT ;
    USE SIGNAL ;
    PORT
      LAYER M4 ;
        RECT  26.916 23.04 27 23.064 ;
    END
  END token[3]
  PIN token[4]
    DIRECTION OUTPUT ;
    USE SIGNAL ;
    PORT
      LAYER M4 ;
        RECT  26.916 23.184 27 23.208 ;
    END
  END token[4]
  PIN token[5]
    DIRECTION OUTPUT ;
    USE SIGNAL ;
    PORT
      LAYER M4 ;
        RECT  26.916 23.328 27 23.352 ;
    END
  END token[5]
  PIN token[6]
    DIRECTION OUTPUT ;
    USE SIGNAL ;
    PORT
      LAYER M4 ;
        RECT  26.916 23.472 27 23.496 ;
    END
  END token[6]
  PIN token[7]
    DIRECTION OUTPUT ;
    USE SIGNAL ;
    PORT
      LAYER M4 ;
        RECT  26.916 23.616 27 23.64 ;
    END
  END token[7]
  PIN token[8]
    DIRECTION OUTPUT ;
    USE SIGNAL ;
    PORT
      LAYER M4 ;
        RECT  26.916 5.328 27 5.352 ;
    END
  END token[8]
  PIN token[9]
    DIRECTION OUTPUT ;
    USE SIGNAL ;
    PORT
      LAYER M4 ;
        RECT  26.916 5.472 27 5.496 ;
    END
  END token[9]
  PIN token_cycles[0]
    DIRECTION OUTPUT ;
    USE SIGNAL ;
    PORT
      LAYER M4 ;
        RECT  26.916 6.768 27 6.792 ;
    END
  END token_cycles[0]
  PIN token_cycles[10]
    DIRECTION OUTPUT ;
    USE SIGNAL ;
    PORT
      LAYER M4 ;
        RECT  26.916 8.208 27 8.232 ;
    END
  END token_cycles[10]
  PIN token_cycles[11]
    DIRECTION OUTPUT ;
    USE SIGNAL ;
    PORT
      LAYER M4 ;
        RECT  26.916 8.352 27 8.376 ;
    END
  END token_cycles[11]
  PIN token_cycles[12]
    DIRECTION OUTPUT ;
    USE SIGNAL ;
    PORT
      LAYER M4 ;
        RECT  26.916 8.496 27 8.52 ;
    END
  END token_cycles[12]
  PIN token_cycles[13]
    DIRECTION OUTPUT ;
    USE SIGNAL ;
    PORT
      LAYER M4 ;
        RECT  26.916 8.64 27 8.664 ;
    END
  END token_cycles[13]
  PIN token_cycles[14]
    DIRECTION OUTPUT ;
    USE SIGNAL ;
    PORT
      LAYER M4 ;
        RECT  26.916 8.784 27 8.808 ;
    END
  END token_cycles[14]
  PIN token_cycles[15]
    DIRECTION OUTPUT ;
    USE SIGNAL ;
    PORT
      LAYER M4 ;
        RECT  26.916 8.928 27 8.952 ;
    END
  END token_cycles[15]
  PIN token_cycles[16]
    DIRECTION OUTPUT ;
    USE SIGNAL ;
    PORT
      LAYER M4 ;
        RECT  26.916 9.072 27 9.096 ;
    END
  END token_cycles[16]
  PIN token_cycles[17]
    DIRECTION OUTPUT ;
    USE SIGNAL ;
    PORT
      LAYER M4 ;
        RECT  26.916 9.216 27 9.24 ;
    END
  END token_cycles[17]
  PIN token_cycles[18]
    DIRECTION OUTPUT ;
    USE SIGNAL ;
    PORT
      LAYER M4 ;
        RECT  26.916 9.36 27 9.384 ;
    END
  END token_cycles[18]
  PIN token_cycles[19]
    DIRECTION OUTPUT ;
    USE SIGNAL ;
    PORT
      LAYER M4 ;
        RECT  26.916 9.504 27 9.528 ;
    END
  END token_cycles[19]
  PIN token_cycles[1]
    DIRECTION OUTPUT ;
    USE SIGNAL ;
    PORT
      LAYER M4 ;
        RECT  26.916 6.912 27 6.936 ;
    END
  END token_cycles[1]
  PIN token_cycles[20]
    DIRECTION OUTPUT ;
    USE SIGNAL ;
    PORT
      LAYER M4 ;
        RECT  26.916 9.648 27 9.672 ;
    END
  END token_cycles[20]
  PIN token_cycles[21]
    DIRECTION OUTPUT ;
    USE SIGNAL ;
    PORT
      LAYER M4 ;
        RECT  26.916 9.792 27 9.816 ;
    END
  END token_cycles[21]
  PIN token_cycles[22]
    DIRECTION OUTPUT ;
    USE SIGNAL ;
    PORT
      LAYER M4 ;
        RECT  26.916 0.72 27 0.744 ;
    END
  END token_cycles[22]
  PIN token_cycles[23]
    DIRECTION OUTPUT ;
    USE SIGNAL ;
    PORT
      LAYER M4 ;
        RECT  26.916 0.864 27 0.888 ;
    END
  END token_cycles[23]
  PIN token_cycles[24]
    DIRECTION OUTPUT ;
    USE SIGNAL ;
    PORT
      LAYER M4 ;
        RECT  26.916 1.008 27 1.032 ;
    END
  END token_cycles[24]
  PIN token_cycles[25]
    DIRECTION OUTPUT ;
    USE SIGNAL ;
    PORT
      LAYER M4 ;
        RECT  26.916 1.152 27 1.176 ;
    END
  END token_cycles[25]
  PIN token_cycles[26]
    DIRECTION OUTPUT ;
    USE SIGNAL ;
    PORT
      LAYER M4 ;
        RECT  26.916 1.296 27 1.32 ;
    END
  END token_cycles[26]
  PIN token_cycles[27]
    DIRECTION OUTPUT ;
    USE SIGNAL ;
    PORT
      LAYER M4 ;
        RECT  26.916 1.44 27 1.464 ;
    END
  END token_cycles[27]
  PIN token_cycles[28]
    DIRECTION OUTPUT ;
    USE SIGNAL ;
    PORT
      LAYER M4 ;
        RECT  26.916 1.584 27 1.608 ;
    END
  END token_cycles[28]
  PIN token_cycles[29]
    DIRECTION OUTPUT ;
    USE SIGNAL ;
    PORT
      LAYER M4 ;
        RECT  26.916 1.728 27 1.752 ;
    END
  END token_cycles[29]
  PIN token_cycles[2]
    DIRECTION OUTPUT ;
    USE SIGNAL ;
    PORT
      LAYER M4 ;
        RECT  26.916 7.056 27 7.08 ;
    END
  END token_cycles[2]
  PIN token_cycles[30]
    DIRECTION OUTPUT ;
    USE SIGNAL ;
    PORT
      LAYER M4 ;
        RECT  26.916 1.872 27 1.896 ;
    END
  END token_cycles[30]
  PIN token_cycles[31]
    DIRECTION OUTPUT ;
    USE SIGNAL ;
    PORT
      LAYER M4 ;
        RECT  26.916 2.016 27 2.04 ;
    END
  END token_cycles[31]
  PIN token_cycles[3]
    DIRECTION OUTPUT ;
    USE SIGNAL ;
    PORT
      LAYER M4 ;
        RECT  26.916 7.2 27 7.224 ;
    END
  END token_cycles[3]
  PIN token_cycles[4]
    DIRECTION OUTPUT ;
    USE SIGNAL ;
    PORT
      LAYER M4 ;
        RECT  26.916 7.344 27 7.368 ;
    END
  END token_cycles[4]
  PIN token_cycles[5]
    DIRECTION OUTPUT ;
    USE SIGNAL ;
    PORT
      LAYER M4 ;
        RECT  26.916 7.488 27 7.512 ;
    END
  END token_cycles[5]
  PIN token_cycles[6]
    DIRECTION OUTPUT ;
    USE SIGNAL ;
    PORT
      LAYER M4 ;
        RECT  26.916 7.632 27 7.656 ;
    END
  END token_cycles[6]
  PIN token_cycles[7]
    DIRECTION OUTPUT ;
    USE SIGNAL ;
    PORT
      LAYER M4 ;
        RECT  26.916 7.776 27 7.8 ;
    END
  END token_cycles[7]
  PIN token_cycles[8]
    DIRECTION OUTPUT ;
    USE SIGNAL ;
    PORT
      LAYER M4 ;
        RECT  26.916 7.92 27 7.944 ;
    END
  END token_cycles[8]
  PIN token_cycles[9]
    DIRECTION OUTPUT ;
    USE SIGNAL ;
    PORT
      LAYER M4 ;
        RECT  26.916 8.064 27 8.088 ;
    END
  END token_cycles[9]
  PIN token_epoch_valid
    DIRECTION INPUT ;
    USE SIGNAL ;
    PORT
      LAYER M4 ;
        RECT  0 23.184 0.084 23.208 ;
    END
  END token_epoch_valid
  PIN vgo
    DIRECTION OUTPUT ;
    USE SIGNAL ;
    PORT
      LAYER M4 ;
        RECT  26.916 2.16 27 2.184 ;
    END
  END vgo
  PIN writer_start
    DIRECTION OUTPUT ;
    USE SIGNAL ;
    PORT
      LAYER M4 ;
        RECT  26.916 2.304 27 2.328 ;
    END
  END writer_start
  PIN VDD
    DIRECTION INOUT ;
    USE POWER ;
    PORT
      LAYER M5 ;
        RECT  24.192 2.151 24.312 35.649 ;
        RECT  21.492 2.151 21.612 35.649 ;
        RECT  18.792 2.151 18.912 35.649 ;
        RECT  16.092 2.151 16.212 35.649 ;
        RECT  13.392 2.151 13.512 35.649 ;
        RECT  10.692 2.151 10.812 35.649 ;
        RECT  7.992 2.151 8.112 35.649 ;
        RECT  5.292 2.151 5.412 35.649 ;
        RECT  2.592 2.151 2.712 35.649 ;
    END
  END VDD
  PIN VSS
    DIRECTION INOUT ;
    USE GROUND ;
    PORT
      LAYER M5 ;
        RECT  24 2.137 24.12 35.663 ;
        RECT  21.3 2.137 21.42 35.663 ;
        RECT  18.6 2.137 18.72 35.663 ;
        RECT  15.9 2.137 16.02 35.663 ;
        RECT  13.2 2.137 13.32 35.663 ;
        RECT  10.5 2.137 10.62 35.663 ;
        RECT  7.8 2.137 7.92 35.663 ;
        RECT  5.1 2.137 5.22 35.663 ;
        RECT  2.4 2.137 2.52 35.663 ;
    END
  END VSS
  OBS
    LAYER RVTN ;
     RECT  2.16 2.16 24.84 2.295 ;
     RECT  2.16 2.565 24.84 2.835 ;
     RECT  2.16 3.105 24.84 3.375 ;
     RECT  2.16 3.645 24.84 3.915 ;
     RECT  2.16 4.185 24.84 4.455 ;
     RECT  2.16 4.725 24.84 4.995 ;
     RECT  2.16 5.265 24.84 5.535 ;
     RECT  2.16 5.805 24.84 6.075 ;
     RECT  2.16 6.345 24.84 6.615 ;
     RECT  2.16 6.885 24.84 7.155 ;
     RECT  2.16 7.425 24.84 7.695 ;
     RECT  2.16 7.965 24.84 8.235 ;
     RECT  2.16 8.505 24.84 8.775 ;
     RECT  2.16 9.045 24.84 9.315 ;
     RECT  2.16 9.585 24.84 9.855 ;
     RECT  2.16 10.125 24.84 10.395 ;
     RECT  2.16 10.665 24.84 10.935 ;
     RECT  2.16 11.205 24.84 11.475 ;
     RECT  2.16 11.745 24.84 12.015 ;
     RECT  2.16 12.285 24.84 12.555 ;
     RECT  2.16 12.825 24.84 13.095 ;
     RECT  2.16 13.365 24.84 13.635 ;
     RECT  2.16 13.905 24.84 14.175 ;
     RECT  2.16 14.445 24.84 14.715 ;
     RECT  2.16 14.985 24.84 15.255 ;
     RECT  2.16 15.525 24.84 15.795 ;
     RECT  2.16 16.065 24.84 16.335 ;
     RECT  2.16 16.605 24.84 16.875 ;
     RECT  2.16 17.145 24.84 17.415 ;
     RECT  2.16 17.685 24.84 17.955 ;
     RECT  2.16 18.225 24.84 18.495 ;
     RECT  2.16 18.765 24.84 19.035 ;
     RECT  2.16 19.305 24.84 19.575 ;
     RECT  2.16 19.845 24.84 20.115 ;
     RECT  2.16 20.385 24.84 20.655 ;
     RECT  2.16 20.925 24.84 21.195 ;
     RECT  2.16 21.465 24.84 21.735 ;
     RECT  2.16 22.005 24.84 22.275 ;
     RECT  2.16 22.545 24.84 22.815 ;
     RECT  2.16 23.085 24.84 23.355 ;
     RECT  2.16 23.625 24.84 23.895 ;
     RECT  2.16 24.165 24.84 24.435 ;
     RECT  2.16 24.705 24.84 24.975 ;
     RECT  2.16 25.245 24.84 25.515 ;
     RECT  2.16 25.785 24.84 26.055 ;
     RECT  2.16 26.325 24.84 26.595 ;
     RECT  2.16 26.865 24.84 27.135 ;
     RECT  2.16 27.405 24.84 27.675 ;
     RECT  2.16 27.945 24.84 28.215 ;
     RECT  2.16 28.485 24.84 28.755 ;
     RECT  2.16 29.025 24.84 29.295 ;
     RECT  2.16 29.565 24.84 29.835 ;
     RECT  2.16 30.105 24.84 30.375 ;
     RECT  2.16 30.645 24.84 30.915 ;
     RECT  2.16 31.185 24.84 31.455 ;
     RECT  2.16 31.725 24.84 31.995 ;
     RECT  2.16 32.265 24.84 32.535 ;
     RECT  2.16 32.805 24.84 33.075 ;
     RECT  2.16 33.345 24.84 33.615 ;
     RECT  2.16 33.885 24.84 34.155 ;
     RECT  2.16 34.425 24.84 34.695 ;
     RECT  2.16 34.965 24.84 35.235 ;
     RECT  2.16 35.505 24.84 35.64 ;
    LAYER RVTP ;
     RECT  2.16 2.295 24.84 2.565 ;
     RECT  2.16 2.835 24.84 3.105 ;
     RECT  2.16 3.375 24.84 3.645 ;
     RECT  2.16 3.915 24.84 4.185 ;
     RECT  2.16 4.455 24.84 4.725 ;
     RECT  2.16 4.995 24.84 5.265 ;
     RECT  2.16 5.535 24.84 5.805 ;
     RECT  2.16 6.075 24.84 6.345 ;
     RECT  2.16 6.615 24.84 6.885 ;
     RECT  2.16 7.155 24.84 7.425 ;
     RECT  2.16 7.695 24.84 7.965 ;
     RECT  2.16 8.235 24.84 8.505 ;
     RECT  2.16 8.775 24.84 9.045 ;
     RECT  2.16 9.315 24.84 9.585 ;
     RECT  2.16 9.855 24.84 10.125 ;
     RECT  2.16 10.395 24.84 10.665 ;
     RECT  2.16 10.935 24.84 11.205 ;
     RECT  2.16 11.475 24.84 11.745 ;
     RECT  2.16 12.015 24.84 12.285 ;
     RECT  2.16 12.555 24.84 12.825 ;
     RECT  2.16 13.095 24.84 13.365 ;
     RECT  2.16 13.635 24.84 13.905 ;
     RECT  2.16 14.175 24.84 14.445 ;
     RECT  2.16 14.715 24.84 14.985 ;
     RECT  2.16 15.255 24.84 15.525 ;
     RECT  2.16 15.795 24.84 16.065 ;
     RECT  2.16 16.335 24.84 16.605 ;
     RECT  2.16 16.875 24.84 17.145 ;
     RECT  2.16 17.415 24.84 17.685 ;
     RECT  2.16 17.955 24.84 18.225 ;
     RECT  2.16 18.495 24.84 18.765 ;
     RECT  2.16 19.035 24.84 19.305 ;
     RECT  2.16 19.575 24.84 19.845 ;
     RECT  2.16 20.115 24.84 20.385 ;
     RECT  2.16 20.655 24.84 20.925 ;
     RECT  2.16 21.195 24.84 21.465 ;
     RECT  2.16 21.735 24.84 22.005 ;
     RECT  2.16 22.275 24.84 22.545 ;
     RECT  2.16 22.815 24.84 23.085 ;
     RECT  2.16 23.355 24.84 23.625 ;
     RECT  2.16 23.895 24.84 24.165 ;
     RECT  2.16 24.435 24.84 24.705 ;
     RECT  2.16 24.975 24.84 25.245 ;
     RECT  2.16 25.515 24.84 25.785 ;
     RECT  2.16 26.055 24.84 26.325 ;
     RECT  2.16 26.595 24.84 26.865 ;
     RECT  2.16 27.135 24.84 27.405 ;
     RECT  2.16 27.675 24.84 27.945 ;
     RECT  2.16 28.215 24.84 28.485 ;
     RECT  2.16 28.755 24.84 29.025 ;
     RECT  2.16 29.295 24.84 29.565 ;
     RECT  2.16 29.835 24.84 30.105 ;
     RECT  2.16 30.375 24.84 30.645 ;
     RECT  2.16 30.915 24.84 31.185 ;
     RECT  2.16 31.455 24.84 31.725 ;
     RECT  2.16 31.995 24.84 32.265 ;
     RECT  2.16 32.535 24.84 32.805 ;
     RECT  2.16 33.075 24.84 33.345 ;
     RECT  2.16 33.615 24.84 33.885 ;
     RECT  2.16 34.155 24.84 34.425 ;
     RECT  2.16 34.695 24.84 34.965 ;
     RECT  2.16 35.235 24.84 35.505 ;
    LAYER M1 ;
     RECT  2.16 2.151 24.84 35.649 ;
    LAYER M2 ;
     RECT  0.103 6.822 2.16 6.84 ;
     RECT  0.103 27.918 2.16 27.936 ;
     RECT  0.103 29.034 2.16 29.052 ;
     RECT  2.16 2.151 12.811 35.649 ;
     RECT  12.811 2.07 17.023 35.649 ;
     RECT  17.023 2.034 22.775 35.649 ;
     RECT  22.775 2.151 24.84 35.649 ;
     RECT  24.84 2.304 25.079 22.806 ;
     RECT  24.84 24.138 25.079 30.294 ;
     RECT  25.079 2.304 25.547 2.754 ;
     RECT  25.079 3.546 25.583 22.806 ;
     RECT  25.547 2.466 25.655 2.754 ;
     RECT  25.583 4.086 25.691 22.806 ;
     RECT  25.079 24.714 25.943 30.294 ;
     RECT  25.943 24.714 25.979 27.972 ;
     RECT  25.655 2.736 26.231 2.754 ;
     RECT  25.691 8.946 26.231 22.806 ;
     RECT  25.979 24.714 26.231 27.774 ;
     RECT  25.943 28.8 26.231 30.294 ;
     RECT  26.231 21.546 26.239 22.806 ;
     RECT  26.231 9.126 26.267 11.844 ;
     RECT  26.231 12.906 26.267 16.164 ;
     RECT  26.231 16.956 26.267 19.296 ;
     RECT  26.231 24.714 26.267 26.622 ;
     RECT  25.691 4.086 26.303 7.956 ;
     RECT  26.267 9.126 26.303 9.954 ;
     RECT  26.267 13.986 26.303 14.202 ;
     RECT  26.267 15.066 26.303 16.164 ;
     RECT  26.267 16.956 26.303 17.514 ;
     RECT  26.231 20.196 26.303 20.646 ;
     RECT  26.267 25.29 26.303 26.622 ;
     RECT  26.231 28.8 26.303 30.204 ;
     RECT  26.303 9.126 26.339 9.612 ;
     RECT  26.303 14.184 26.339 14.202 ;
     RECT  26.303 17.388 26.339 17.514 ;
     RECT  26.239 21.546 26.339 22.842 ;
     RECT  26.231 27.756 26.339 27.774 ;
     RECT  26.267 13.176 26.375 13.194 ;
     RECT  26.303 25.29 26.411 26.514 ;
     RECT  26.303 28.8 26.735 30.024 ;
     RECT  26.303 20.556 26.843 20.646 ;
     RECT  26.411 25.866 26.843 26.514 ;
     RECT  26.735 30.006 26.843 30.024 ;
     RECT  26.303 4.086 26.879 6.876 ;
     RECT  26.843 20.592 26.879 20.646 ;
     RECT  26.735 28.8 26.879 29.214 ;
     RECT  26.879 4.086 26.915 4.104 ;
     RECT  26.879 5.076 26.915 5.094 ;
     RECT  26.303 7.938 26.915 7.956 ;
     RECT  26.339 9.126 26.915 9.144 ;
     RECT  26.267 11.826 26.915 11.844 ;
     RECT  26.303 15.534 26.915 15.552 ;
     RECT  26.339 17.496 26.915 17.514 ;
     RECT  26.267 18.306 26.915 18.792 ;
     RECT  26.879 20.628 26.915 20.646 ;
     RECT  26.339 22.248 26.915 22.266 ;
     RECT  26.843 25.866 26.915 25.884 ;
     RECT  26.879 28.8 26.915 28.818 ;
     RECT  26.879 6.156 26.951 6.876 ;
    LAYER M3 ;
     RECT  25.344 0.715 25.362 0.859 ;
     RECT  25.344 0.859 25.65 1.147 ;
     RECT  26.892 1.003 26.91 1.147 ;
     RECT  25.344 1.147 26.91 1.435 ;
     RECT  25.056 1.435 26.91 1.723 ;
     RECT  18.576 2.029 18.81 2.065 ;
     RECT  17.028 2.029 17.046 2.101 ;
     RECT  12.816 2.065 12.834 2.143 ;
     RECT  13.788 2.065 13.806 2.143 ;
     RECT  21.744 2.101 21.762 2.143 ;
     RECT  24.552 1.723 26.91 2.143 ;
     RECT  14.976 2.101 14.994 2.191 ;
     RECT  24.015 2.143 26.91 2.191 ;
     RECT  15.915 2.143 16.005 2.251 ;
     RECT  17.028 2.101 17.334 2.251 ;
     RECT  11.844 1.723 11.862 2.255 ;
     RECT  22.752 2.029 22.77 2.263 ;
     RECT  23.976 2.191 26.91 2.263 ;
     RECT  14.868 2.191 14.994 2.299 ;
     RECT  18.576 2.065 18.954 2.299 ;
     RECT  21.315 2.143 21.762 2.299 ;
     RECT  12.06 2.263 12.078 2.335 ;
     RECT  12.816 2.143 13.806 2.335 ;
     RECT  14.688 2.299 14.994 2.335 ;
     RECT  15.732 2.251 17.334 2.335 ;
     RECT  18.108 2.299 19.35 2.335 ;
     RECT  20.988 2.299 21.762 2.335 ;
     RECT  12.06 2.335 19.494 2.371 ;
     RECT  20.376 2.335 21.762 2.371 ;
     RECT  22.536 2.263 22.77 2.371 ;
     RECT  23.796 2.263 26.91 2.371 ;
     RECT  12.06 2.371 26.91 2.381 ;
     RECT  2.415 2.143 2.505 2.413 ;
     RECT  5.115 2.143 5.205 2.413 ;
     RECT  7.815 2.143 7.905 2.413 ;
     RECT  10.515 2.143 10.605 2.413 ;
     RECT  12.06 2.381 12.258 2.489 ;
     RECT  12.996 2.381 26.91 2.759 ;
     RECT  9.36 2.731 9.378 2.767 ;
     RECT  7.815 2.413 8.097 2.839 ;
     RECT  9.108 2.767 9.378 2.839 ;
     RECT  7.815 2.839 9.378 2.911 ;
     RECT  12.132 2.489 12.258 3.109 ;
     RECT  12.996 2.759 25.578 3.109 ;
     RECT  7.815 2.911 9.522 3.181 ;
     RECT  10.515 2.413 10.797 3.181 ;
     RECT  5.115 2.413 5.397 3.271 ;
     RECT  10.476 3.181 10.797 3.304 ;
     RECT  4.68 3.271 5.397 3.343 ;
     RECT  7.815 3.181 9.63 3.403 ;
     RECT  7.812 3.403 9.63 3.415 ;
     RECT  4.572 3.343 5.397 3.451 ;
     RECT  6.84 3.181 6.858 3.451 ;
     RECT  7.776 3.415 9.63 3.451 ;
     RECT  10.476 3.304 11.394 3.451 ;
     RECT  12.132 3.109 25.578 3.569 ;
     RECT  4.572 3.451 5.922 3.721 ;
     RECT  6.84 3.451 11.394 3.721 ;
     RECT  12.132 3.569 25.362 3.721 ;
     RECT  2.415 2.413 2.697 3.739 ;
     RECT  4.572 3.721 25.362 3.839 ;
     RECT  4.572 3.839 6.102 3.991 ;
     RECT  26.82 2.759 26.91 4.109 ;
     RECT  7.02 3.839 24.534 4.415 ;
     RECT  7.02 4.415 24.498 4.559 ;
     RECT  25.344 3.839 25.362 4.559 ;
     RECT  3.564 3.991 6.102 4.621 ;
     RECT  26.82 4.109 26.874 4.693 ;
     RECT  2.304 3.739 2.697 4.765 ;
     RECT  3.564 4.621 6.21 4.765 ;
     RECT  2.304 4.765 6.21 4.801 ;
     RECT  7.02 4.559 21.654 4.801 ;
     RECT  2.304 4.801 21.654 4.919 ;
     RECT  2.304 4.919 2.697 4.955 ;
     RECT  3.42 4.919 21.654 4.955 ;
     RECT  26.208 4.693 26.874 5.071 ;
     RECT  26.208 5.071 26.91 5.233 ;
     RECT  4.536 4.955 21.654 5.341 ;
     RECT  22.392 4.559 24.498 5.341 ;
     RECT  4.536 5.341 24.498 5.503 ;
     RECT  25.632 5.233 26.91 5.503 ;
     RECT  4.536 5.503 26.91 5.645 ;
     RECT  3.42 4.955 3.798 5.701 ;
     RECT  4.536 5.645 24.714 5.701 ;
     RECT  2.34 4.955 2.697 5.737 ;
     RECT  3.42 5.701 24.714 5.737 ;
     RECT  2.34 5.737 24.714 5.899 ;
     RECT  25.632 5.645 26.91 6.077 ;
     RECT  26.208 6.077 26.91 6.151 ;
     RECT  26.208 6.151 26.946 6.881 ;
     RECT  26.208 6.881 26.874 6.961 ;
     RECT  0.108 6.817 0.126 7.085 ;
     RECT  2.304 5.899 24.714 7.159 ;
     RECT  25.668 6.961 26.874 7.159 ;
     RECT  2.304 7.159 26.874 7.229 ;
     RECT  2.304 7.229 24.534 7.349 ;
     RECT  2.304 7.349 24.498 7.619 ;
     RECT  25.668 7.229 26.874 7.933 ;
     RECT  2.304 7.619 2.697 8.059 ;
     RECT  2.268 8.059 2.697 8.195 ;
     RECT  25.668 7.933 26.91 8.237 ;
     RECT  2.304 8.195 2.697 8.303 ;
     RECT  25.668 8.237 26.874 8.303 ;
     RECT  2.34 8.303 2.697 8.465 ;
     RECT  2.376 8.465 2.697 8.581 ;
     RECT  3.42 7.619 24.498 8.581 ;
     RECT  2.376 8.581 24.498 8.699 ;
     RECT  2.376 8.699 2.697 8.735 ;
     RECT  3.492 8.699 24.498 8.735 ;
     RECT  3.708 8.735 24.498 8.743 ;
     RECT  3.708 8.743 25.074 9.005 ;
     RECT  26.172 8.303 26.874 9.067 ;
     RECT  26.172 9.067 26.91 9.149 ;
     RECT  3.852 9.005 25.074 9.581 ;
     RECT  26.172 9.149 26.334 9.617 ;
     RECT  2.415 8.735 2.697 9.691 ;
     RECT  3.852 9.581 24.57 9.779 ;
     RECT  26.172 9.617 26.298 9.787 ;
     RECT  2.415 9.691 2.754 9.895 ;
     RECT  25.668 9.787 26.298 9.959 ;
     RECT  2.415 9.895 3.042 10.049 ;
     RECT  3.852 9.779 24.498 10.165 ;
     RECT  25.668 9.959 26.262 10.193 ;
     RECT  2.415 10.049 2.862 10.319 ;
     RECT  3.816 10.165 24.498 10.651 ;
     RECT  3.816 10.651 25.074 10.891 ;
     RECT  3.672 10.891 25.074 11.129 ;
     RECT  26.172 10.193 26.262 11.227 ;
     RECT  3.852 11.129 25.074 11.273 ;
     RECT  26.172 11.227 26.91 11.371 ;
     RECT  3.852 11.273 24.498 11.543 ;
     RECT  25.668 11.371 26.91 11.849 ;
     RECT  3.924 11.543 24.498 12.091 ;
     RECT  25.668 11.849 26.226 12.091 ;
     RECT  3.924 12.091 26.226 12.389 ;
     RECT  3.924 12.389 25.326 12.427 ;
     RECT  26.172 12.389 26.226 12.479 ;
     RECT  26.208 12.479 26.226 12.667 ;
     RECT  26.208 12.667 26.262 12.955 ;
     RECT  3.852 12.427 25.326 13.063 ;
     RECT  3.744 13.063 25.326 13.133 ;
     RECT  26.208 12.955 26.298 13.171 ;
     RECT  2.415 10.319 2.697 13.243 ;
     RECT  3.744 13.133 25.074 13.369 ;
     RECT  2.415 13.243 2.826 13.441 ;
     RECT  3.672 13.369 25.074 13.441 ;
     RECT  26.208 13.171 26.37 13.829 ;
     RECT  2.415 13.441 25.074 13.937 ;
     RECT  2.415 13.937 2.862 13.945 ;
     RECT  3.6 13.937 25.074 14.099 ;
     RECT  2.376 13.945 2.862 14.251 ;
     RECT  26.244 13.829 26.37 14.285 ;
     RECT  25.056 14.099 25.074 14.521 ;
     RECT  2.304 14.251 2.862 14.675 ;
     RECT  25.056 14.521 25.11 14.683 ;
     RECT  26.244 14.285 26.262 14.683 ;
     RECT  2.415 14.675 2.862 14.779 ;
     RECT  3.6 14.099 24.297 14.779 ;
     RECT  2.415 14.779 24.297 14.881 ;
     RECT  25.056 14.683 26.262 14.881 ;
     RECT  2.415 14.881 26.262 15.061 ;
     RECT  2.415 15.061 26.298 15.287 ;
     RECT  2.415 15.287 25.074 15.403 ;
     RECT  2.304 15.403 25.074 15.493 ;
     RECT  26.208 15.287 26.298 15.529 ;
     RECT  2.268 15.493 25.074 15.725 ;
     RECT  2.304 15.725 25.074 16.097 ;
     RECT  26.208 15.529 26.91 16.367 ;
     RECT  2.304 16.097 25.038 17.275 ;
     RECT  2.268 17.275 25.074 17.563 ;
     RECT  26.244 16.367 26.91 17.563 ;
     RECT  2.268 17.563 26.91 17.645 ;
     RECT  2.304 17.645 26.91 18.059 ;
     RECT  2.304 18.059 24.642 18.455 ;
     RECT  2.412 18.455 24.642 18.725 ;
     RECT  0.108 18.571 0.126 18.749 ;
     RECT  2.415 18.725 24.642 18.859 ;
     RECT  25.632 18.059 26.91 18.859 ;
     RECT  2.415 18.859 26.91 18.959 ;
     RECT  2.415 18.959 25.074 19.571 ;
     RECT  26.208 18.959 26.91 19.867 ;
     RECT  25.56 19.867 26.91 20.651 ;
     RECT  2.415 19.571 24.57 20.731 ;
     RECT  25.56 20.651 26.334 20.731 ;
     RECT  2.415 20.731 26.334 20.965 ;
     RECT  2.304 20.965 26.334 22.001 ;
     RECT  2.304 22.001 25.722 22.037 ;
     RECT  2.304 22.037 24.57 22.171 ;
     RECT  2.268 22.171 24.57 22.235 ;
     RECT  25.668 22.037 25.722 22.493 ;
     RECT  26.892 22.171 26.91 22.783 ;
     RECT  2.304 22.235 24.57 23.035 ;
     RECT  2.304 23.035 25.038 23.323 ;
     RECT  2.304 23.323 25.074 23.755 ;
     RECT  2.304 23.755 25.47 24.043 ;
     RECT  26.244 22.783 26.91 24.043 ;
     RECT  0.324 24.763 0.342 24.941 ;
     RECT  2.304 24.043 26.91 25.439 ;
     RECT  2.304 25.439 21.942 25.475 ;
     RECT  22.824 25.439 26.91 26.285 ;
     RECT  2.304 25.475 21.906 26.401 ;
     RECT  2.304 26.401 22.266 26.491 ;
     RECT  23.22 26.285 26.91 26.519 ;
     RECT  2.268 26.491 22.266 27.139 ;
     RECT  23.724 26.519 26.91 27.301 ;
     RECT  2.268 27.139 22.59 27.337 ;
     RECT  2.268 27.337 22.662 27.707 ;
     RECT  2.304 27.707 22.662 27.751 ;
     RECT  23.472 27.301 26.91 27.751 ;
     RECT  0.108 27.913 0.126 27.965 ;
     RECT  0.144 28.651 0.162 28.781 ;
     RECT  2.304 27.751 26.91 28.823 ;
     RECT  2.304 28.823 26.874 28.859 ;
     RECT  2.304 28.859 25.362 28.985 ;
     RECT  2.304 28.985 23.166 29.021 ;
     RECT  0.108 29.029 0.126 29.117 ;
     RECT  26.208 28.859 26.874 29.219 ;
     RECT  23.94 28.985 25.362 29.597 ;
     RECT  23.94 29.597 24.642 29.759 ;
     RECT  23.94 29.759 24.606 30.029 ;
     RECT  26.208 29.219 26.838 30.029 ;
     RECT  22.716 29.021 23.166 30.109 ;
     RECT  23.94 30.029 24.297 30.109 ;
     RECT  0.324 29.947 0.342 30.125 ;
     RECT  26.208 30.029 26.298 30.209 ;
     RECT  2.304 29.021 21.906 30.235 ;
     RECT  2.232 30.235 21.906 30.271 ;
     RECT  22.716 30.109 24.297 30.271 ;
     RECT  26.208 30.209 26.226 30.299 ;
     RECT  2.232 30.271 24.297 30.335 ;
     RECT  2.268 30.335 24.297 30.569 ;
     RECT  2.268 30.569 22.05 30.875 ;
     RECT  2.268 30.875 21.978 30.947 ;
     RECT  2.268 30.947 21.87 31.145 ;
     RECT  23.148 30.569 24.297 31.721 ;
     RECT  2.304 31.145 21.87 31.765 ;
     RECT  23.04 31.765 23.058 31.919 ;
     RECT  0.144 31.147 0.162 32.429 ;
     RECT  2.304 31.765 22.158 32.459 ;
     RECT  2.304 32.459 22.014 32.495 ;
     RECT  2.34 32.495 11.142 32.729 ;
     RECT  11.952 32.495 22.014 32.729 ;
     RECT  2.34 32.729 10.998 32.765 ;
     RECT  11.952 32.729 21.597 32.765 ;
     RECT  21.168 32.765 21.597 32.801 ;
     RECT  11.988 32.765 20.43 32.999 ;
     RECT  20.412 32.999 20.43 33.071 ;
     RECT  11.988 32.999 19.098 33.143 ;
     RECT  2.415 32.765 10.89 33.269 ;
     RECT  11.988 33.143 18.897 33.305 ;
     RECT  3.744 33.269 5.67 33.341 ;
     RECT  5.076 33.341 5.67 33.449 ;
     RECT  3.744 33.341 4.302 33.539 ;
     RECT  5.076 33.449 5.397 33.539 ;
     RECT  11.988 33.305 17.73 33.539 ;
     RECT  3.744 33.539 4.158 33.575 ;
     RECT  11.988 33.539 17.694 33.611 ;
     RECT  14.76 33.611 17.514 33.647 ;
     RECT  11.988 33.611 13.806 33.683 ;
     RECT  14.796 33.647 17.514 33.809 ;
     RECT  11.988 33.683 13.497 33.817 ;
     RECT  6.552 33.269 10.89 33.961 ;
     RECT  11.736 33.817 13.497 33.961 ;
     RECT  6.552 33.961 13.497 34.151 ;
     RECT  6.84 34.151 13.497 34.655 ;
     RECT  14.796 33.809 17.046 34.699 ;
     RECT  7.092 34.655 13.497 34.727 ;
     RECT  14.796 34.699 17.19 34.735 ;
     RECT  9.432 34.727 13.497 34.763 ;
     RECT  12.168 34.763 13.497 34.771 ;
     RECT  9.432 34.763 11.43 34.889 ;
     RECT  12.168 34.771 13.59 34.889 ;
     RECT  14.616 34.735 17.19 34.889 ;
     RECT  12.348 34.889 13.497 34.925 ;
     RECT  7.092 34.727 8.658 34.961 ;
     RECT  7.092 34.961 8.55 35.033 ;
     RECT  7.596 35.033 8.55 35.159 ;
     RECT  12.708 34.925 13.497 35.159 ;
     RECT  14.616 34.889 16.794 35.159 ;
     RECT  9.432 34.889 11.286 35.195 ;
     RECT  13.104 35.159 13.497 35.195 ;
     RECT  15.408 35.159 16.794 35.195 ;
     RECT  7.596 35.159 8.097 35.213 ;
     RECT  9.432 35.195 9.45 35.213 ;
     RECT  14.616 35.159 14.634 35.303 ;
     RECT  15.408 35.195 16.197 35.303 ;
     RECT  10.515 35.195 11.286 35.339 ;
     RECT  2.415 33.269 2.697 35.387 ;
     RECT  5.115 33.539 5.397 35.387 ;
     RECT  7.815 35.213 8.097 35.387 ;
     RECT  10.515 35.339 10.797 35.387 ;
     RECT  13.215 35.195 13.497 35.387 ;
     RECT  15.915 35.303 16.197 35.387 ;
     RECT  18.615 33.305 18.897 35.387 ;
     RECT  21.315 32.801 21.597 35.387 ;
     RECT  24.015 31.721 24.297 35.387 ;
     RECT  2.415 35.387 2.505 35.657 ;
     RECT  5.115 35.387 5.205 35.657 ;
     RECT  7.815 35.387 7.905 35.657 ;
     RECT  10.515 35.387 10.605 35.657 ;
     RECT  13.215 35.387 13.305 35.657 ;
     RECT  15.915 35.387 16.005 35.657 ;
     RECT  18.615 35.387 18.705 35.657 ;
     RECT  21.315 35.387 21.405 35.657 ;
     RECT  24.015 35.387 24.105 35.657 ;
    LAYER M4 ;
     RECT  0.06 15.264 0.097 18.6 ;
     RECT  0.06 21.024 0.173 32.424 ;
     RECT  0.06 3.744 2.408 4.632 ;
     RECT  0.06 5.616 2.408 8.232 ;
     RECT  0.06 14.112 2.408 14.28 ;
     RECT  0.097 15.264 2.408 18.744 ;
     RECT  0.173 21.024 2.408 32.328 ;
     RECT  2.408 2.148 2.512 35.652 ;
     RECT  2.512 2.418 2.704 35.382 ;
     RECT  2.704 5.76 2.765 5.784 ;
     RECT  2.704 7.2 2.765 7.224 ;
     RECT  2.704 17.424 2.765 22.776 ;
     RECT  2.704 26.64 2.873 26.664 ;
     RECT  2.765 17.424 2.909 21.672 ;
     RECT  2.704 25.488 2.909 25.512 ;
     RECT  2.704 12.336 2.915 14.904 ;
     RECT  2.704 15.984 2.981 16.152 ;
     RECT  2.909 17.424 3.017 17.448 ;
     RECT  2.704 30.048 3.125 32.328 ;
     RECT  2.915 14.784 3.197 14.904 ;
     RECT  2.704 27.648 3.197 27.672 ;
     RECT  2.909 18.72 3.233 21.672 ;
     RECT  2.704 28.752 3.341 28.824 ;
     RECT  3.233 19.248 3.521 21.672 ;
     RECT  3.521 19.248 3.629 20.568 ;
     RECT  2.981 16.128 3.805 16.152 ;
     RECT  3.341 28.8 3.864 28.824 ;
     RECT  3.125 30.048 3.864 30.264 ;
     RECT  3.841 8.544 3.877 8.568 ;
     RECT  2.704 9.696 3.881 9.72 ;
     RECT  3.521 21.648 3.925 21.672 ;
     RECT  3.913 22.8 3.925 22.824 ;
     RECT  2.915 12.336 3.985 12.456 ;
     RECT  3.125 31.872 4.057 32.328 ;
     RECT  3.805 16.128 4.097 17.016 ;
     RECT  4.057 31.872 4.129 32.472 ;
     RECT  4.097 16.128 4.201 16.584 ;
     RECT  4.129 31.872 4.237 33.096 ;
     RECT  3.197 14.784 4.309 14.808 ;
     RECT  4.201 16.032 4.309 16.584 ;
     RECT  4.021 27.072 4.309 27.096 ;
     RECT  4.309 14.784 4.345 16.584 ;
     RECT  4.309 26.208 4.381 27.096 ;
     RECT  4.273 17.616 4.417 17.64 ;
     RECT  3.629 19.248 4.417 20.088 ;
     RECT  4.309 5.712 4.453 5.736 ;
     RECT  3.733 24.48 4.489 24.504 ;
     RECT  3.925 21.648 4.561 22.824 ;
     RECT  4.561 21.648 4.597 22.92 ;
     RECT  4.489 24.192 4.597 24.504 ;
     RECT  4.597 21.648 4.633 24.504 ;
     RECT  4.633 21.648 4.669 25.176 ;
     RECT  4.381 26.208 4.669 27.384 ;
     RECT  3.864 28.8 4.813 30.264 ;
     RECT  4.417 17.616 4.921 20.088 ;
     RECT  4.525 9.792 4.957 9.816 ;
     RECT  2.704 10.896 4.957 10.92 ;
     RECT  4.669 21.648 4.957 27.384 ;
     RECT  4.957 21.648 5.029 27.48 ;
     RECT  4.453 5.712 5.108 6.84 ;
     RECT  3.877 8.448 5.108 8.568 ;
     RECT  4.957 9.792 5.108 10.92 ;
     RECT  3.985 12.336 5.108 13.128 ;
     RECT  4.345 14.4 5.108 16.584 ;
     RECT  4.921 17.616 5.108 20.424 ;
     RECT  5.029 21.648 5.108 27.672 ;
     RECT  4.813 28.8 5.108 30.36 ;
     RECT  4.237 31.344 5.108 33.096 ;
     RECT  5.108 2.148 5.212 35.652 ;
     RECT  5.212 2.418 5.404 35.382 ;
     RECT  5.404 19.248 5.609 30.984 ;
     RECT  5.609 19.872 5.933 30.984 ;
     RECT  5.933 19.872 6.329 20.184 ;
     RECT  5.933 21.264 6.329 30.984 ;
     RECT  5.404 7.872 6.433 10.92 ;
     RECT  5.404 13.44 6.433 18.216 ;
     RECT  5.404 4.848 6.469 4.872 ;
     RECT  6.433 13.008 6.545 18.216 ;
     RECT  5.404 6.096 6.577 6.84 ;
     RECT  6.433 7.872 6.577 11.592 ;
     RECT  5.404 32.448 6.581 33.672 ;
     RECT  6.469 4.848 6.613 5.112 ;
     RECT  6.577 6.096 6.613 11.592 ;
     RECT  6.329 19.872 6.649 20.088 ;
     RECT  6.545 16.032 6.653 18.216 ;
     RECT  6.653 17.664 6.689 18.216 ;
     RECT  6.329 22.032 6.689 30.984 ;
     RECT  6.689 26.304 6.749 30.984 ;
     RECT  6.581 32.448 6.749 32.76 ;
     RECT  6.749 26.304 6.833 32.76 ;
     RECT  6.649 19.824 6.937 20.088 ;
     RECT  5.404 3.84 6.965 3.864 ;
     RECT  6.613 4.848 6.965 11.592 ;
     RECT  6.937 19.392 7.441 20.088 ;
     RECT  7.441 18.72 7.477 20.088 ;
     RECT  6.689 22.032 7.477 25.32 ;
     RECT  6.689 17.664 7.765 17.688 ;
     RECT  6.965 3.84 7.801 11.592 ;
     RECT  7.801 3.408 7.808 11.592 ;
     RECT  6.545 13.008 7.808 14.904 ;
     RECT  6.653 16.032 7.808 16.104 ;
     RECT  7.765 17.424 7.808 17.688 ;
     RECT  7.477 18.72 7.808 25.32 ;
     RECT  6.833 26.304 7.808 29.928 ;
     RECT  6.833 31.2 7.808 31.224 ;
     RECT  6.833 32.4 7.808 32.76 ;
     RECT  7.585 35.184 7.808 35.208 ;
     RECT  7.808 2.148 7.912 35.652 ;
     RECT  7.912 2.418 8.104 35.382 ;
     RECT  8.104 29.232 8.345 32.76 ;
     RECT  8.104 13.104 8.453 13.416 ;
     RECT  8.453 13.392 8.597 13.416 ;
     RECT  8.104 21.12 8.597 22.296 ;
     RECT  8.104 26.304 8.675 28.152 ;
     RECT  8.104 14.4 8.705 14.76 ;
     RECT  8.675 27.984 8.716 28.152 ;
     RECT  8.345 29.232 8.749 29.64 ;
     RECT  8.104 6.816 8.777 7.416 ;
     RECT  8.104 4.944 8.849 5.784 ;
     RECT  8.345 30.768 9.065 32.76 ;
     RECT  8.104 3.408 9.097 3.96 ;
     RECT  8.104 17.424 9.097 17.592 ;
     RECT  8.104 18.576 9.097 20.088 ;
     RECT  8.104 10.896 9.133 11.304 ;
     RECT  8.705 14.688 9.133 14.76 ;
     RECT  8.104 15.984 9.133 16.104 ;
     RECT  8.104 34.128 9.155 35.208 ;
     RECT  8.749 29.232 9.169 29.304 ;
     RECT  9.133 10.896 9.205 11.4 ;
     RECT  8.104 24.48 9.205 25.128 ;
     RECT  8.675 26.304 9.205 26.808 ;
     RECT  9.097 2.88 9.209 3.96 ;
     RECT  8.849 5.76 9.209 5.784 ;
     RECT  9.133 14.688 9.209 16.104 ;
     RECT  9.097 17.424 9.209 20.088 ;
     RECT  9.097 13.584 9.245 13.608 ;
     RECT  9.209 18.72 9.281 20.088 ;
     RECT  8.597 21.408 9.313 22.296 ;
     RECT  9.281 18.72 9.317 19.656 ;
     RECT  9.205 24.192 9.317 26.808 ;
     RECT  9.209 14.736 9.349 16.104 ;
     RECT  9.209 17.424 9.349 17.592 ;
     RECT  9.169 29.184 9.425 29.304 ;
     RECT  8.777 7.056 9.452 7.416 ;
     RECT  9.155 34.56 9.461 35.208 ;
     RECT  9.452 7.056 9.493 7.944 ;
     RECT  8.104 9.36 9.493 9.576 ;
     RECT  9.065 31.392 9.497 32.76 ;
     RECT  9.493 7.056 9.533 9.576 ;
     RECT  9.533 7.152 9.539 9.576 ;
     RECT  9.313 21.408 9.601 22.824 ;
     RECT  9.539 8.784 9.673 9.576 ;
     RECT  9.673 8.784 9.925 9.72 ;
     RECT  9.205 10.896 9.925 12.312 ;
     RECT  9.317 25.104 9.961 26.808 ;
     RECT  8.716 27.984 9.961 28.008 ;
     RECT  9.497 31.392 10.069 31.896 ;
     RECT  10.069 31.104 10.249 31.896 ;
     RECT  9.349 14.736 10.277 17.592 ;
     RECT  9.601 21.12 10.293 22.824 ;
     RECT  9.317 18.72 10.321 19.56 ;
     RECT  10.293 20.592 10.321 22.824 ;
     RECT  10.277 13.872 10.357 17.592 ;
     RECT  10.321 18.72 10.357 22.824 ;
     RECT  9.209 3.312 10.508 3.96 ;
     RECT  9.601 6 10.508 6.024 ;
     RECT  9.539 7.152 10.508 7.224 ;
     RECT  9.925 8.784 10.508 12.312 ;
     RECT  10.357 13.872 10.508 17.64 ;
     RECT  10.357 18.72 10.508 23.16 ;
     RECT  9.961 25.104 10.508 28.008 ;
     RECT  9.425 29.28 10.508 29.304 ;
     RECT  10.249 30.768 10.508 31.896 ;
     RECT  9.74 32.928 10.508 32.952 ;
     RECT  9.461 34.56 10.508 34.776 ;
     RECT  10.508 2.148 10.612 35.652 ;
     RECT  10.612 2.418 10.804 35.382 ;
     RECT  10.804 28.992 10.901 29.304 ;
     RECT  10.804 15.216 10.973 22.296 ;
     RECT  10.804 25.44 11.045 28.008 ;
     RECT  10.804 30.864 11.045 31.752 ;
     RECT  10.804 34.224 11.117 34.776 ;
     RECT  11.045 31.104 11.189 31.752 ;
     RECT  10.973 15.216 11.333 22.056 ;
     RECT  10.804 3.312 11.405 4.008 ;
     RECT  11.189 31.728 11.405 31.752 ;
     RECT  10.804 8.784 11.449 13.896 ;
     RECT  11.333 17.088 11.549 22.056 ;
     RECT  10.804 7.392 11.797 7.416 ;
     RECT  11.045 25.44 11.836 27.624 ;
     RECT  11.449 8.784 11.843 13.656 ;
     RECT  10.901 28.992 11.869 29.256 ;
     RECT  11.789 1.728 11.873 1.752 ;
     RECT  11.797 6.816 11.881 7.416 ;
     RECT  10.804 23.328 11.941 23.352 ;
     RECT  11.836 25.44 11.987 26.472 ;
     RECT  11.405 3.6 12.017 4.008 ;
     RECT  11.941 23.328 12.017 24.312 ;
     RECT  10.804 5.136 12.049 5.304 ;
     RECT  12.049 5.136 12.085 5.592 ;
     RECT  11.869 28.992 12.113 29.352 ;
     RECT  12.017 3.6 12.131 3.864 ;
     RECT  12.113 28.992 12.197 29.688 ;
     RECT  12.017 24.288 12.229 24.312 ;
     RECT  11.987 25.44 12.229 25.464 ;
     RECT  12.197 28.992 12.233 29.352 ;
     RECT  11.117 34.224 12.337 34.248 ;
     RECT  11.843 9.024 12.445 13.656 ;
     RECT  12.085 4.992 12.517 5.592 ;
     RECT  11.836 27.504 12.517 27.624 ;
     RECT  11.333 15.216 12.553 16.104 ;
     RECT  11.549 17.088 12.553 20.52 ;
     RECT  11.987 26.448 12.805 26.472 ;
     RECT  12.517 27.504 12.805 27.768 ;
     RECT  12.805 26.448 12.877 27.768 ;
     RECT  12.085 2.352 13.057 2.376 ;
     RECT  12.131 3.6 13.057 3.768 ;
     RECT  12.517 4.992 13.093 6.072 ;
     RECT  11.881 7.392 13.093 7.416 ;
     RECT  12.445 9.024 13.093 14.184 ;
     RECT  12.553 15.216 13.093 20.52 ;
     RECT  13.093 9.024 13.165 20.52 ;
     RECT  13.057 2.352 13.208 3.768 ;
     RECT  13.093 4.992 13.208 7.416 ;
     RECT  13.165 9.024 13.208 20.712 ;
     RECT  11.549 22.032 13.208 22.056 ;
     RECT  12.229 24.288 13.208 25.464 ;
     RECT  12.877 26.448 13.208 28.008 ;
     RECT  12.233 29.232 13.208 29.352 ;
     RECT  12.769 31.392 13.208 31.416 ;
     RECT  12.337 34.224 13.208 34.92 ;
     RECT  13.208 2.148 13.312 35.652 ;
     RECT  13.312 2.352 13.504 35.382 ;
     RECT  13.504 2.352 13.529 16.104 ;
     RECT  13.504 18.528 13.529 21.144 ;
     RECT  13.504 27.168 13.619 28.008 ;
     RECT  13.504 30.624 13.637 31.416 ;
     RECT  13.529 2.352 13.709 3.72 ;
     RECT  13.637 30.864 13.745 31.416 ;
     RECT  13.504 33.552 13.745 33.576 ;
     RECT  13.529 18.72 13.781 21.144 ;
     RECT  13.529 4.704 14.177 16.104 ;
     RECT  13.781 18.72 14.285 20.76 ;
     RECT  13.709 2.352 14.429 2.376 ;
     RECT  13.504 22.176 14.497 23.304 ;
     RECT  14.497 22.176 14.569 24.072 ;
     RECT  13.504 25.776 14.605 25.8 ;
     RECT  13.709 3.696 14.641 3.72 ;
     RECT  13.504 29.328 14.641 29.544 ;
     RECT  13.745 31.392 14.641 31.416 ;
     RECT  14.569 22.176 14.677 24.264 ;
     RECT  14.605 25.68 14.677 25.8 ;
     RECT  13.504 17.088 14.749 17.544 ;
     RECT  14.641 29.184 14.749 29.544 ;
     RECT  14.641 31.392 14.749 32.04 ;
     RECT  14.177 4.992 14.785 16.104 ;
     RECT  14.749 17.088 14.785 17.832 ;
     RECT  14.641 3.696 14.821 3.816 ;
     RECT  14.749 30.768 14.861 32.04 ;
     RECT  13.619 27.84 14.965 27.864 ;
     RECT  14.677 22.176 15.109 25.8 ;
     RECT  14.821 2.496 15.181 3.816 ;
     RECT  14.785 4.992 15.181 17.832 ;
     RECT  15.109 22.176 15.253 25.848 ;
     RECT  15.181 2.496 15.289 17.832 ;
     RECT  14.285 18.816 15.289 20.76 ;
     RECT  14.861 32.016 15.505 32.04 ;
     RECT  15.253 33.552 15.505 33.576 ;
     RECT  15.289 2.496 15.541 20.76 ;
     RECT  15.253 21.792 15.541 25.848 ;
     RECT  15.541 2.496 15.613 25.848 ;
     RECT  14.965 27.84 15.685 27.912 ;
     RECT  15.613 2.496 15.721 26.136 ;
     RECT  15.685 27.84 15.757 27.96 ;
     RECT  14.749 28.992 15.757 29.544 ;
     RECT  15.721 2.256 15.908 26.136 ;
     RECT  15.757 27.84 15.908 29.544 ;
     RECT  14.861 30.768 15.908 30.792 ;
     RECT  15.505 32.016 15.908 33.576 ;
     RECT  13.504 34.896 15.908 34.92 ;
     RECT  15.908 2.148 16.012 35.652 ;
     RECT  16.012 2.256 16.204 35.382 ;
     RECT  16.204 32.304 16.265 32.328 ;
     RECT  16.204 33.36 16.337 34.92 ;
     RECT  16.337 33.36 16.355 33.864 ;
     RECT  16.337 34.896 16.355 34.92 ;
     RECT  16.204 3.6 16.445 26.232 ;
     RECT  16.445 3.648 16.589 26.232 ;
     RECT  16.355 33.36 16.697 33.384 ;
     RECT  16.589 3.648 16.877 23.64 ;
     RECT  16.877 4.08 16.949 23.64 ;
     RECT  16.204 27.216 17.057 29.64 ;
     RECT  17.057 28.992 17.123 29.64 ;
     RECT  16.204 2.256 17.165 2.616 ;
     RECT  16.949 4.08 17.165 4.44 ;
     RECT  17.057 27.216 17.165 27.96 ;
     RECT  16.589 24.672 17.377 26.232 ;
     RECT  17.165 27.216 17.377 27.912 ;
     RECT  17.165 2.448 17.413 2.616 ;
     RECT  17.377 24.672 17.453 27.912 ;
     RECT  17.123 29.04 17.489 29.64 ;
     RECT  16.204 31.008 17.521 31.032 ;
     RECT  17.521 30.336 17.633 31.032 ;
     RECT  17.413 2.448 17.953 3.048 ;
     RECT  17.165 4.08 17.953 4.2 ;
     RECT  17.953 2.448 18.241 4.2 ;
     RECT  17.453 24.72 18.277 27.912 ;
     RECT  17.489 29.04 18.277 29.256 ;
     RECT  18.241 2.448 18.608 4.44 ;
     RECT  16.949 5.76 18.608 23.64 ;
     RECT  18.277 24.72 18.608 29.256 ;
     RECT  17.809 31.152 18.608 31.176 ;
     RECT  18.608 2.148 18.712 35.652 ;
     RECT  18.712 2.418 18.904 35.382 ;
     RECT  18.904 2.496 18.929 26.088 ;
     RECT  18.904 30.72 19.001 31.464 ;
     RECT  18.929 2.496 19.037 25.848 ;
     RECT  19.001 30.816 19.073 31.464 ;
     RECT  19.037 2.496 19.145 25.56 ;
     RECT  19.145 6.048 19.541 25.56 ;
     RECT  19.541 6.24 19.865 25.56 ;
     RECT  19.073 31.104 19.933 31.464 ;
     RECT  18.904 27.12 20.005 27.432 ;
     RECT  18.904 28.464 20.005 29.4 ;
     RECT  19.933 31.104 20.153 32.232 ;
     RECT  19.865 13.008 20.189 25.56 ;
     RECT  20.189 14.496 20.195 25.56 ;
     RECT  20.153 31.104 20.329 31.464 ;
     RECT  20.195 21.696 20.437 25.56 ;
     RECT  20.329 31.056 20.437 31.464 ;
     RECT  20.005 27.12 20.617 29.4 ;
     RECT  20.437 21.696 21.013 25.8 ;
     RECT  20.617 26.784 21.013 29.4 ;
     RECT  19.145 2.496 21.308 5.016 ;
     RECT  19.865 6.24 21.308 11.784 ;
     RECT  20.189 13.008 21.308 13.416 ;
     RECT  20.195 14.496 21.308 20.712 ;
     RECT  21.013 21.696 21.308 29.4 ;
     RECT  20.437 30.816 21.308 31.464 ;
     RECT  20.437 32.496 21.308 32.52 ;
     RECT  21.308 2.148 21.412 35.652 ;
     RECT  21.412 2.418 21.604 35.382 ;
     RECT  21.604 2.496 21.665 2.52 ;
     RECT  21.604 23.28 21.701 27.912 ;
     RECT  21.604 15.264 21.737 17.544 ;
     RECT  21.701 24.672 21.737 27.432 ;
     RECT  21.737 26.064 21.773 27.432 ;
     RECT  21.737 15.264 21.809 16.296 ;
     RECT  21.604 4.512 21.845 4.536 ;
     RECT  21.604 18.72 21.845 19.8 ;
     RECT  21.773 27.12 21.845 27.432 ;
     RECT  21.604 21.696 21.881 21.72 ;
     RECT  21.604 6.384 21.917 7.368 ;
     RECT  21.845 27.168 21.953 27.432 ;
     RECT  21.737 24.672 21.989 24.696 ;
     RECT  21.604 9.408 22.061 10.344 ;
     RECT  21.604 11.664 22.061 11.688 ;
     RECT  21.604 13.056 22.133 13.656 ;
     RECT  21.737 17.52 22.133 17.544 ;
     RECT  21.845 19.632 22.169 19.8 ;
     RECT  21.917 7.344 22.241 7.368 ;
     RECT  21.701 23.28 22.601 23.304 ;
     RECT  21.953 27.408 22.673 27.432 ;
     RECT  22.133 13.296 22.921 13.656 ;
     RECT  22.061 9.408 22.925 9.432 ;
     RECT  21.809 15.264 23.029 16.104 ;
     RECT  22.921 13.296 23.033 14.184 ;
     RECT  22.169 19.632 23.461 19.656 ;
     RECT  23.641 7.632 23.785 7.656 ;
     RECT  22.633 22.128 23.785 22.152 ;
     RECT  23.785 22.032 23.821 22.152 ;
     RECT  23.785 7.632 24.008 7.944 ;
     RECT  23.033 13.296 24.008 13.56 ;
     RECT  23.029 15.168 24.008 16.104 ;
     RECT  22.813 17.616 24.008 17.64 ;
     RECT  23.461 19.296 24.008 19.656 ;
     RECT  23.857 20.688 24.008 20.712 ;
     RECT  23.821 21.744 24.008 22.152 ;
     RECT  23.137 27.888 24.008 27.912 ;
     RECT  24.008 2.148 24.112 35.652 ;
     RECT  24.112 2.148 24.304 35.382 ;
     RECT  24.304 20.688 24.437 23.352 ;
     RECT  24.541 1.728 25.045 2.04 ;
     RECT  25.045 1.44 25.333 2.04 ;
     RECT  24.304 24.336 25.333 24.792 ;
     RECT  24.304 26.496 25.333 28.104 ;
     RECT  24.437 20.736 25.405 23.352 ;
     RECT  25.333 24.336 25.405 28.104 ;
     RECT  25.333 0.72 25.513 2.04 ;
     RECT  24.304 12.24 25.549 19.464 ;
     RECT  25.405 20.736 25.549 28.104 ;
     RECT  25.549 12.24 25.621 28.104 ;
     RECT  24.304 5.616 25.657 7.944 ;
     RECT  24.304 8.928 25.657 9.528 ;
     RECT  24.304 10.656 25.657 11.112 ;
     RECT  25.621 12.096 25.657 28.104 ;
     RECT  25.657 5.616 26.161 28.104 ;
     RECT  26.161 5.472 26.197 28.104 ;
     RECT  25.513 0.72 26.94 2.328 ;
     RECT  26.197 5.328 26.94 28.248 ;
    LAYER M5 ;
     RECT  2.4 2.137 2.52 2.151 ;
     RECT  5.1 2.137 5.22 2.151 ;
     RECT  7.8 2.137 7.92 2.151 ;
     RECT  10.5 2.137 10.62 2.151 ;
     RECT  11.664 0.016 11.832 2.151 ;
     RECT  13.2 2.137 13.32 2.151 ;
     RECT  15.9 2.137 16.02 2.151 ;
     RECT  18.6 2.137 18.72 2.151 ;
     RECT  21.3 2.137 21.42 2.151 ;
     RECT  24 2.137 24.12 2.151 ;
     RECT  10.5 2.151 11.832 2.341 ;
     RECT  15.9 2.151 16.212 2.821 ;
     RECT  7.8 2.151 8.112 4.501 ;
     RECT  15.792 2.821 16.212 4.979 ;
     RECT  13.2 2.151 13.512 4.981 ;
     RECT  10.5 2.341 12.12 5.027 ;
     RECT  7.008 4.501 8.112 5.123 ;
     RECT  15.9 4.979 16.212 6.037 ;
     RECT  5.1 2.151 5.412 6.085 ;
     RECT  5.1 6.085 6.312 6.229 ;
     RECT  7.8 5.123 8.112 6.229 ;
     RECT  5.1 6.229 8.112 6.275 ;
     RECT  13.104 4.981 13.512 6.707 ;
     RECT  10.5 5.027 11.688 6.805 ;
     RECT  18.6 2.151 18.912 8.485 ;
     RECT  9.504 7.909 9.528 8.819 ;
     RECT  5.1 6.275 5.412 8.821 ;
     RECT  15.9 6.037 16.344 9.061 ;
     RECT  10.5 6.805 11.832 9.445 ;
     RECT  18.6 8.485 19.032 9.683 ;
     RECT  15.9 9.061 17.256 9.779 ;
     RECT  9.984 9.445 11.832 9.925 ;
     RECT  9.984 9.925 12.216 10.307 ;
     RECT  6.816 6.275 8.112 10.837 ;
     RECT  10.5 10.307 12.216 10.837 ;
     RECT  13.2 6.707 13.512 10.837 ;
     RECT  6.576 10.837 8.112 10.883 ;
     RECT  15.9 9.779 16.344 10.885 ;
     RECT  5.1 8.821 5.544 10.931 ;
     RECT  10.5 10.837 13.512 11.221 ;
     RECT  10.5 11.221 13.608 11.411 ;
     RECT  15.9 10.885 16.824 11.509 ;
     RECT  14.928 11.509 16.824 11.749 ;
     RECT  14.832 11.749 16.824 11.795 ;
     RECT  14.832 11.795 14.856 11.987 ;
     RECT  2.4 2.151 2.712 12.325 ;
     RECT  6.576 10.883 6.6 13.045 ;
     RECT  7.8 10.883 8.112 13.045 ;
     RECT  10.5 11.411 13.512 13.861 ;
     RECT  5.1 10.931 5.412 14.389 ;
     RECT  6.576 13.045 8.112 14.389 ;
     RECT  2.4 12.325 2.904 14.915 ;
     RECT  5.1 14.389 8.112 14.915 ;
     RECT  10.32 13.861 13.512 14.917 ;
     RECT  10.272 14.917 13.512 15.205 ;
     RECT  9.648 15.205 13.512 15.253 ;
     RECT  9.36 15.253 13.512 15.493 ;
     RECT  9.168 15.493 13.512 15.731 ;
     RECT  5.1 14.915 6.312 16.595 ;
     RECT  18.6 9.683 18.912 16.837 ;
     RECT  15.9 11.795 16.824 16.885 ;
     RECT  9.36 15.731 13.512 17.077 ;
     RECT  15.168 16.885 16.824 17.077 ;
     RECT  5.1 16.595 5.592 17.123 ;
     RECT  9.36 17.077 16.824 17.125 ;
     RECT  9.36 17.125 17.16 17.267 ;
     RECT  9.36 17.267 16.824 17.363 ;
     RECT  9.36 17.363 14.472 17.555 ;
     RECT  15.9 17.363 16.824 17.699 ;
     RECT  18.6 16.837 19.032 18.563 ;
     RECT  9.36 17.555 13.512 18.851 ;
     RECT  15.9 17.699 16.212 18.997 ;
     RECT  2.4 14.915 2.712 19.237 ;
     RECT  14.976 18.997 16.212 19.475 ;
     RECT  12.144 18.851 13.512 20.005 ;
     RECT  12.144 20.005 14.376 20.243 ;
     RECT  18.6 18.563 18.912 20.293 ;
     RECT  2.4 19.237 3.432 20.579 ;
     RECT  15.792 19.475 16.212 20.725 ;
     RECT  7.8 14.915 8.112 21.013 ;
     RECT  18.24 20.293 18.912 21.395 ;
     RECT  20.16 20.389 20.184 21.971 ;
     RECT  5.1 17.123 5.412 22.021 ;
     RECT  12.144 20.243 13.512 22.021 ;
     RECT  7.488 21.013 8.112 22.067 ;
     RECT  3.936 22.021 3.96 22.835 ;
     RECT  9.36 18.851 10.92 22.835 ;
     RECT  15.264 20.725 16.212 23.987 ;
     RECT  18.6 21.395 18.912 24.469 ;
     RECT  0.144 24.901 0.168 25.043 ;
     RECT  18.6 24.469 19.032 25.091 ;
     RECT  6.768 23.173 6.792 25.141 ;
     RECT  15.9 23.987 16.212 25.141 ;
     RECT  6.576 25.141 6.792 25.427 ;
     RECT  15.9 25.141 17.16 26.243 ;
     RECT  11.952 22.021 13.512 26.483 ;
     RECT  10.272 22.835 10.92 26.725 ;
     RECT  11.952 26.483 12.216 26.725 ;
     RECT  7.8 22.067 8.112 27.157 ;
     RECT  13.2 26.483 13.512 27.157 ;
     RECT  15.9 26.243 16.212 27.301 ;
     RECT  13.2 27.157 13.608 28.019 ;
     RECT  7.8 27.157 8.664 28.163 ;
     RECT  18.6 25.091 18.912 28.453 ;
     RECT  15.9 27.301 16.632 28.981 ;
     RECT  15.9 28.981 17.112 29.123 ;
     RECT  10.272 26.725 12.216 29.219 ;
     RECT  15.9 29.123 17.016 29.221 ;
     RECT  10.272 29.219 12.168 29.267 ;
     RECT  18.6 28.453 19.464 29.411 ;
     RECT  7.8 28.163 8.112 29.605 ;
     RECT  12.144 29.267 12.168 29.699 ;
     RECT  0.144 30.085 0.168 30.227 ;
     RECT  3.936 29.509 3.96 30.275 ;
     RECT  15.36 29.221 17.016 30.803 ;
     RECT  21.3 2.151 21.612 30.805 ;
     RECT  7.8 29.605 8.712 30.851 ;
     RECT  15.9 30.803 17.016 31.043 ;
     RECT  6.768 25.427 6.792 31.189 ;
     RECT  7.8 30.851 8.112 31.189 ;
     RECT  10.272 29.267 10.812 31.717 ;
     RECT  6.768 31.189 8.112 31.955 ;
     RECT  7.68 31.955 8.112 32.435 ;
     RECT  20.448 30.805 21.612 32.531 ;
     RECT  5.1 22.021 5.544 33.013 ;
     RECT  15.9 31.043 16.584 33.395 ;
     RECT  5.1 33.013 6.312 33.683 ;
     RECT  9.792 31.717 10.812 34.117 ;
     RECT  9.12 34.117 10.812 34.787 ;
     RECT  15.9 33.395 16.344 34.931 ;
     RECT  9.12 34.787 9.144 35.219 ;
     RECT  2.4 20.579 2.712 35.649 ;
     RECT  5.1 33.683 5.412 35.649 ;
     RECT  7.8 32.435 8.112 35.649 ;
     RECT  10.5 34.787 10.812 35.649 ;
     RECT  13.2 28.019 13.512 35.649 ;
     RECT  15.9 34.931 16.212 35.649 ;
     RECT  18.6 29.411 18.912 35.649 ;
     RECT  21.3 32.531 21.612 35.649 ;
     RECT  24 2.151 24.312 35.649 ;
     RECT  2.4 35.649 2.52 35.663 ;
     RECT  5.1 35.649 5.22 35.663 ;
     RECT  7.8 35.649 7.92 35.663 ;
     RECT  10.5 35.649 10.62 35.663 ;
     RECT  13.2 35.649 13.32 35.663 ;
     RECT  15.9 35.649 16.02 35.663 ;
     RECT  18.6 35.649 18.72 35.663 ;
     RECT  21.3 35.649 21.42 35.663 ;
     RECT  24 35.649 24.12 35.663 ;
  END
END qkd_static_kv_layer_programme_img
END LIBRARY
